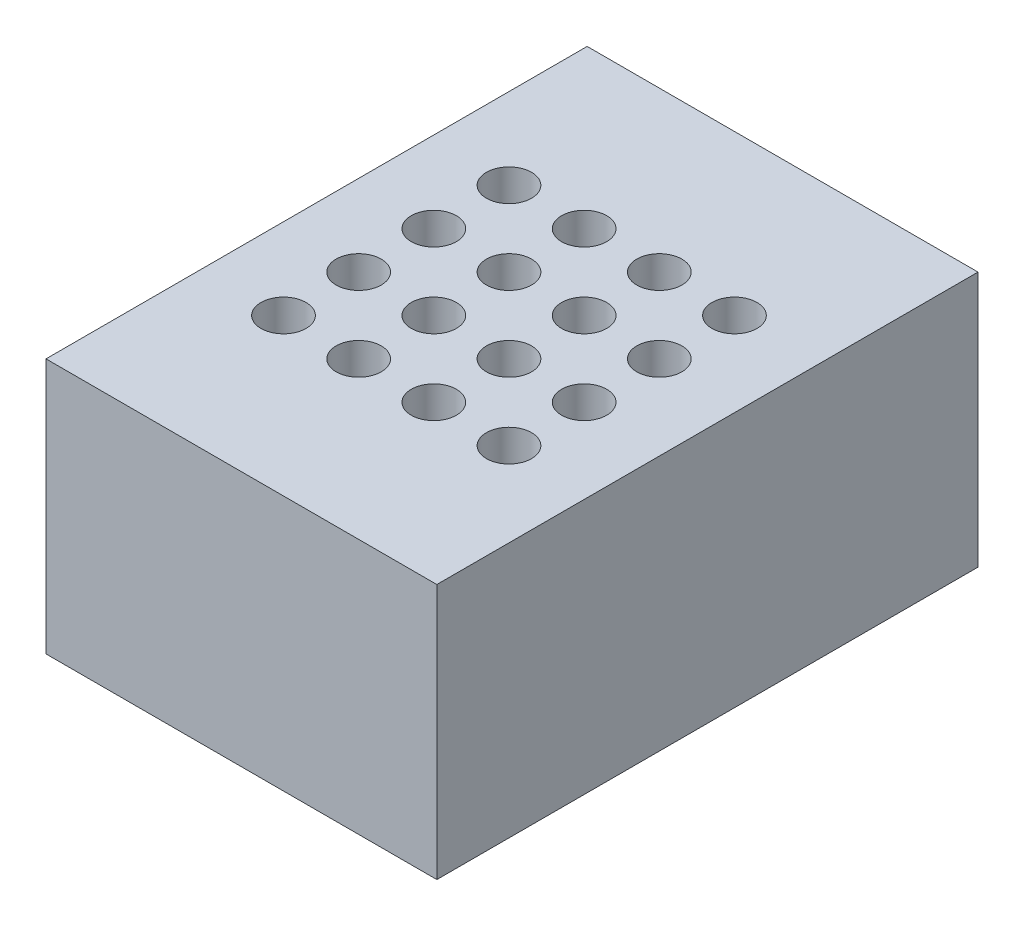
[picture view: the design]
ISO-10303-21;
HEADER;
FILE_DESCRIPTION(('STEP AP214'),'2;1');
FILE_NAME('part.step','',(''),(''),'','','');
FILE_SCHEMA(('AUTOMOTIVE_DESIGN { 1 0 10303 214 1 1 1 1 }'));
ENDSEC;
DATA;
#1=APPLICATION_CONTEXT('core data for automotive mechanical design processes');
#2=APPLICATION_PROTOCOL_DEFINITION('international standard','automotive_design',2000,#1);
#3=PRODUCT_CONTEXT('',#1,'mechanical');
#4=PRODUCT('Part','Part','',(#3));
#5=PRODUCT_RELATED_PRODUCT_CATEGORY('part','',(#4));
#6=PRODUCT_DEFINITION_FORMATION('','',#4);
#7=PRODUCT_DEFINITION_CONTEXT('part definition',#1,'design');
#8=PRODUCT_DEFINITION('design','',#6,#7);
#9=PRODUCT_DEFINITION_SHAPE('','',#8);
#10=(LENGTH_UNIT() NAMED_UNIT(*) SI_UNIT(.MILLI.,.METRE.));
#11=(NAMED_UNIT(*) PLANE_ANGLE_UNIT() SI_UNIT($,.RADIAN.));
#12=(NAMED_UNIT(*) SI_UNIT($,.STERADIAN.) SOLID_ANGLE_UNIT());
#13=UNCERTAINTY_MEASURE_WITH_UNIT(LENGTH_MEASURE(1.E-05),#10,'distance_accuracy_value','');
#14=(GEOMETRIC_REPRESENTATION_CONTEXT(3) GLOBAL_UNCERTAINTY_ASSIGNED_CONTEXT((#13)) GLOBAL_UNIT_ASSIGNED_CONTEXT((#10,
#11,#12)) REPRESENTATION_CONTEXT('',''));
#15=CARTESIAN_POINT('',(0.,0.,0.));
#16=DIRECTION('',(0.,0.,1.));
#17=DIRECTION('',(1.,0.,0.));
#18=AXIS2_PLACEMENT_3D('',#15,#16,#17);
#19=CARTESIAN_POINT('',(0.,8.5,0.));
#20=DIRECTION('',(1.,0.,0.));
#21=DIRECTION('',(0.,0.,-1.));
#22=AXIS2_PLACEMENT_3D('',#19,#20,#21);
#23=PLANE('',#22);
#24=DIRECTION('',(0.,0.,1.));
#25=VECTOR('',#24,1.);
#26=CARTESIAN_POINT('',(0.,0.,0.));
#27=LINE('',#26,#25);
#28=CARTESIAN_POINT('',(0.,0.,-18.));
#29=VERTEX_POINT('',#28);
#30=CARTESIAN_POINT('',(0.,0.,0.));
#31=VERTEX_POINT('',#30);
#32=EDGE_CURVE('E95',#29,#31,#27,.T.);
#33=ORIENTED_EDGE('',*,*,#32,.T.);
#34=DIRECTION('',(0.,-1.,0.));
#35=VECTOR('',#34,1.);
#36=CARTESIAN_POINT('',(0.,8.5,0.));
#37=LINE('',#36,#35);
#38=CARTESIAN_POINT('',(0.,8.5,0.));
#39=VERTEX_POINT('',#38);
#40=EDGE_CURVE('E11',#39,#31,#37,.T.);
#41=ORIENTED_EDGE('',*,*,#40,.F.);
#42=DIRECTION('',(0.,0.,1.));
#43=VECTOR('',#42,1.);
#44=CARTESIAN_POINT('',(0.,8.5,0.));
#45=LINE('',#44,#43);
#46=CARTESIAN_POINT('',(0.,8.5,-18.));
#47=VERTEX_POINT('',#46);
#48=EDGE_CURVE('E83',#47,#39,#45,.T.);
#49=ORIENTED_EDGE('',*,*,#48,.F.);
#50=DIRECTION('',(0.,-1.,0.));
#51=VECTOR('',#50,1.);
#52=CARTESIAN_POINT('',(0.,8.5,-18.));
#53=LINE('',#52,#51);
#54=EDGE_CURVE('E91',#47,#29,#53,.T.);
#55=ORIENTED_EDGE('',*,*,#54,.T.);
#56=EDGE_LOOP('',(#33,#41,#49,#55));
#57=FACE_BOUND('',#56,.T.);
#58=ADVANCED_FACE('F32',(#57),#23,.F.);
#59=CARTESIAN_POINT('',(0.,8.5,0.));
#60=DIRECTION('',(0.,0.,-1.));
#61=DIRECTION('',(-1.,0.,0.));
#62=AXIS2_PLACEMENT_3D('',#59,#60,#61);
#63=PLANE('',#62);
#64=DIRECTION('',(1.,0.,0.));
#65=VECTOR('',#64,1.);
#66=CARTESIAN_POINT('',(0.,0.,0.));
#67=LINE('',#66,#65);
#68=CARTESIAN_POINT('',(13.,0.,0.));
#69=VERTEX_POINT('',#68);
#70=EDGE_CURVE('E87',#31,#69,#67,.T.);
#71=ORIENTED_EDGE('',*,*,#70,.T.);
#72=DIRECTION('',(0.,-1.,0.));
#73=VECTOR('',#72,1.);
#74=CARTESIAN_POINT('',(13.,8.5,0.));
#75=LINE('',#74,#73);
#76=CARTESIAN_POINT('',(13.,8.5,0.));
#77=VERTEX_POINT('',#76);
#78=EDGE_CURVE('E40',#77,#69,#75,.T.);
#79=ORIENTED_EDGE('',*,*,#78,.F.);
#80=DIRECTION('',(1.,0.,0.));
#81=VECTOR('',#80,1.);
#82=CARTESIAN_POINT('',(0.,8.5,0.));
#83=LINE('',#82,#81);
#84=EDGE_CURVE('E78',#39,#77,#83,.T.);
#85=ORIENTED_EDGE('',*,*,#84,.F.);
#86=ORIENTED_EDGE('',*,*,#40,.T.);
#87=EDGE_LOOP('',(#71,#79,#85,#86));
#88=FACE_BOUND('',#87,.T.);
#89=ADVANCED_FACE('F86',(#88),#63,.F.);
#90=CARTESIAN_POINT('',(13.,8.5,0.));
#91=DIRECTION('',(-1.,0.,0.));
#92=DIRECTION('',(0.,0.,1.));
#93=AXIS2_PLACEMENT_3D('',#90,#91,#92);
#94=PLANE('',#93);
#95=DIRECTION('',(0.,0.,-1.));
#96=VECTOR('',#95,1.);
#97=CARTESIAN_POINT('',(13.,0.,0.));
#98=LINE('',#97,#96);
#99=CARTESIAN_POINT('',(13.,0.,-18.));
#100=VERTEX_POINT('',#99);
#101=EDGE_CURVE('E65',#69,#100,#98,.T.);
#102=ORIENTED_EDGE('',*,*,#101,.T.);
#103=DIRECTION('',(0.,-1.,0.));
#104=VECTOR('',#103,1.);
#105=CARTESIAN_POINT('',(13.,8.5,-18.));
#106=LINE('',#105,#104);
#107=CARTESIAN_POINT('',(13.,8.5,-18.));
#108=VERTEX_POINT('',#107);
#109=EDGE_CURVE('E88',#108,#100,#106,.T.);
#110=ORIENTED_EDGE('',*,*,#109,.F.);
#111=DIRECTION('',(0.,0.,-1.));
#112=VECTOR('',#111,1.);
#113=CARTESIAN_POINT('',(13.,8.5,0.));
#114=LINE('',#113,#112);
#115=EDGE_CURVE('E81',#77,#108,#114,.T.);
#116=ORIENTED_EDGE('',*,*,#115,.F.);
#117=ORIENTED_EDGE('',*,*,#78,.T.);
#118=EDGE_LOOP('',(#102,#110,#116,#117));
#119=FACE_BOUND('',#118,.T.);
#120=ADVANCED_FACE('F89',(#119),#94,.F.);
#121=CARTESIAN_POINT('',(0.,8.5,-18.));
#122=DIRECTION('',(0.,0.,1.));
#123=DIRECTION('',(1.,0.,0.));
#124=AXIS2_PLACEMENT_3D('',#121,#122,#123);
#125=PLANE('',#124);
#126=DIRECTION('',(-1.,0.,0.));
#127=VECTOR('',#126,1.);
#128=CARTESIAN_POINT('',(0.,0.,-18.));
#129=LINE('',#128,#127);
#130=EDGE_CURVE('E71',#100,#29,#129,.T.);
#131=ORIENTED_EDGE('',*,*,#130,.T.);
#132=ORIENTED_EDGE('',*,*,#54,.F.);
#133=DIRECTION('',(-1.,0.,0.));
#134=VECTOR('',#133,1.);
#135=CARTESIAN_POINT('',(0.,8.5,-18.));
#136=LINE('',#135,#134);
#137=EDGE_CURVE('E48',#108,#47,#136,.T.);
#138=ORIENTED_EDGE('',*,*,#137,.F.);
#139=ORIENTED_EDGE('',*,*,#109,.T.);
#140=EDGE_LOOP('',(#131,#132,#138,#139));
#141=FACE_BOUND('',#140,.T.);
#142=ADVANCED_FACE('F103',(#141),#125,.F.);
#143=CARTESIAN_POINT('',(0.,8.5,0.));
#144=DIRECTION('',(0.,-1.,0.));
#145=DIRECTION('',(0.,0.,-1.));
#146=AXIS2_PLACEMENT_3D('',#143,#144,#145);
#147=PLANE('',#146);
#148=CARTESIAN_POINT('',(10.2000000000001,8.5,-5.2));
#149=DIRECTION('',(0.,1.,0.));
#150=DIRECTION('',(0.,0.,1.));
#151=AXIS2_PLACEMENT_3D('',#148,#149,#150);
#152=CIRCLE('',#151,0.75);
#153=CARTESIAN_POINT('',(10.2000000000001,8.5,-4.45));
#154=VERTEX_POINT('',#153);
#155=EDGE_CURVE('E199',#154,#154,#152,.T.);
#156=ORIENTED_EDGE('',*,*,#155,.F.);
#157=EDGE_LOOP('',(#156));
#158=FACE_BOUND('',#157,.T.);
#159=CARTESIAN_POINT('',(10.2000000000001,8.5,-7.7));
#160=DIRECTION('',(0.,1.,0.));
#161=DIRECTION('',(0.,0.,1.));
#162=AXIS2_PLACEMENT_3D('',#159,#160,#161);
#163=CIRCLE('',#162,0.75);
#164=CARTESIAN_POINT('',(10.2000000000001,8.5,-6.95));
#165=VERTEX_POINT('',#164);
#166=EDGE_CURVE('E193',#165,#165,#163,.T.);
#167=ORIENTED_EDGE('',*,*,#166,.F.);
#168=EDGE_LOOP('',(#167));
#169=FACE_BOUND('',#168,.T.);
#170=CARTESIAN_POINT('',(10.2,8.5,-10.2));
#171=DIRECTION('',(0.,1.,0.));
#172=DIRECTION('',(0.,0.,1.));
#173=AXIS2_PLACEMENT_3D('',#170,#171,#172);
#174=CIRCLE('',#173,0.75);
#175=CARTESIAN_POINT('',(10.2,8.5,-9.45));
#176=VERTEX_POINT('',#175);
#177=EDGE_CURVE('E187',#176,#176,#174,.T.);
#178=ORIENTED_EDGE('',*,*,#177,.F.);
#179=EDGE_LOOP('',(#178));
#180=FACE_BOUND('',#179,.T.);
#181=CARTESIAN_POINT('',(2.70000000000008,8.5,-5.19999999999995));
#182=DIRECTION('',(0.,1.,0.));
#183=DIRECTION('',(0.,0.,1.));
#184=AXIS2_PLACEMENT_3D('',#181,#182,#183);
#185=CIRCLE('',#184,0.75);
#186=CARTESIAN_POINT('',(2.70000000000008,8.5,-4.44999999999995));
#187=VERTEX_POINT('',#186);
#188=EDGE_CURVE('E181',#187,#187,#185,.T.);
#189=ORIENTED_EDGE('',*,*,#188,.F.);
#190=EDGE_LOOP('',(#189));
#191=FACE_BOUND('',#190,.T.);
#192=CARTESIAN_POINT('',(5.20000000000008,8.5,-5.19999999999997));
#193=DIRECTION('',(0.,1.,0.));
#194=DIRECTION('',(0.,0.,1.));
#195=AXIS2_PLACEMENT_3D('',#192,#193,#194);
#196=CIRCLE('',#195,0.75);
#197=CARTESIAN_POINT('',(5.20000000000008,8.5,-4.44999999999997));
#198=VERTEX_POINT('',#197);
#199=EDGE_CURVE('E175',#198,#198,#196,.T.);
#200=ORIENTED_EDGE('',*,*,#199,.F.);
#201=EDGE_LOOP('',(#200));
#202=FACE_BOUND('',#201,.T.);
#203=CARTESIAN_POINT('',(7.70000000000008,8.5,-5.19999999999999));
#204=DIRECTION('',(0.,1.,0.));
#205=DIRECTION('',(0.,0.,1.));
#206=AXIS2_PLACEMENT_3D('',#203,#204,#205);
#207=CIRCLE('',#206,0.750000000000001);
#208=CARTESIAN_POINT('',(7.70000000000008,8.5,-4.44999999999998));
#209=VERTEX_POINT('',#208);
#210=EDGE_CURVE('E169',#209,#209,#207,.T.);
#211=ORIENTED_EDGE('',*,*,#210,.F.);
#212=EDGE_LOOP('',(#211));
#213=FACE_BOUND('',#212,.T.);
#214=CARTESIAN_POINT('',(2.70000000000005,8.5,-7.69999999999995));
#215=DIRECTION('',(0.,1.,0.));
#216=DIRECTION('',(0.,0.,1.));
#217=AXIS2_PLACEMENT_3D('',#214,#215,#216);
#218=CIRCLE('',#217,0.75);
#219=CARTESIAN_POINT('',(2.70000000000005,8.5,-6.94999999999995));
#220=VERTEX_POINT('',#219);
#221=EDGE_CURVE('E163',#220,#220,#218,.T.);
#222=ORIENTED_EDGE('',*,*,#221,.F.);
#223=EDGE_LOOP('',(#222));
#224=FACE_BOUND('',#223,.T.);
#225=CARTESIAN_POINT('',(5.20000000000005,8.5,-7.69999999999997));
#226=DIRECTION('',(0.,1.,0.));
#227=DIRECTION('',(0.,0.,1.));
#228=AXIS2_PLACEMENT_3D('',#225,#226,#227);
#229=CIRCLE('',#228,0.75);
#230=CARTESIAN_POINT('',(5.20000000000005,8.5,-6.94999999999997));
#231=VERTEX_POINT('',#230);
#232=EDGE_CURVE('E157',#231,#231,#229,.T.);
#233=ORIENTED_EDGE('',*,*,#232,.F.);
#234=EDGE_LOOP('',(#233));
#235=FACE_BOUND('',#234,.T.);
#236=CARTESIAN_POINT('',(7.70000000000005,8.5,-7.69999999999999));
#237=DIRECTION('',(0.,1.,0.));
#238=DIRECTION('',(0.,0.,1.));
#239=AXIS2_PLACEMENT_3D('',#236,#237,#238);
#240=CIRCLE('',#239,0.749999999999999);
#241=CARTESIAN_POINT('',(7.70000000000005,8.5,-6.94999999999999));
#242=VERTEX_POINT('',#241);
#243=EDGE_CURVE('E151',#242,#242,#240,.T.);
#244=ORIENTED_EDGE('',*,*,#243,.F.);
#245=EDGE_LOOP('',(#244));
#246=FACE_BOUND('',#245,.T.);
#247=CARTESIAN_POINT('',(2.70000000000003,8.5,-10.1999999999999));
#248=DIRECTION('',(0.,1.,0.));
#249=DIRECTION('',(0.,0.,1.));
#250=AXIS2_PLACEMENT_3D('',#247,#248,#249);
#251=CIRCLE('',#250,0.75);
#252=CARTESIAN_POINT('',(2.70000000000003,8.5,-9.44999999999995));
#253=VERTEX_POINT('',#252);
#254=EDGE_CURVE('E145',#253,#253,#251,.T.);
#255=ORIENTED_EDGE('',*,*,#254,.F.);
#256=EDGE_LOOP('',(#255));
#257=FACE_BOUND('',#256,.T.);
#258=CARTESIAN_POINT('',(5.20000000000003,8.5,-10.2));
#259=DIRECTION('',(0.,1.,0.));
#260=DIRECTION('',(0.,0.,1.));
#261=AXIS2_PLACEMENT_3D('',#258,#259,#260);
#262=CIRCLE('',#261,0.75);
#263=CARTESIAN_POINT('',(5.20000000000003,8.5,-9.44999999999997));
#264=VERTEX_POINT('',#263);
#265=EDGE_CURVE('E139',#264,#264,#262,.T.);
#266=ORIENTED_EDGE('',*,*,#265,.F.);
#267=EDGE_LOOP('',(#266));
#268=FACE_BOUND('',#267,.T.);
#269=CARTESIAN_POINT('',(7.70000000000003,8.5,-10.2));
#270=DIRECTION('',(0.,1.,0.));
#271=DIRECTION('',(0.,0.,1.));
#272=AXIS2_PLACEMENT_3D('',#269,#270,#271);
#273=CIRCLE('',#272,0.75);
#274=CARTESIAN_POINT('',(7.70000000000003,8.5,-9.44999999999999));
#275=VERTEX_POINT('',#274);
#276=EDGE_CURVE('E133',#275,#275,#273,.T.);
#277=ORIENTED_EDGE('',*,*,#276,.F.);
#278=EDGE_LOOP('',(#277));
#279=FACE_BOUND('',#278,.T.);
#280=CARTESIAN_POINT('',(2.7,8.5,-12.7));
#281=DIRECTION('',(0.,1.,0.));
#282=DIRECTION('',(0.,0.,1.));
#283=AXIS2_PLACEMENT_3D('',#280,#281,#282);
#284=CIRCLE('',#283,0.75);
#285=CARTESIAN_POINT('',(2.7,8.5,-11.9499999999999));
#286=VERTEX_POINT('',#285);
#287=EDGE_CURVE('E127',#286,#286,#284,.T.);
#288=ORIENTED_EDGE('',*,*,#287,.F.);
#289=EDGE_LOOP('',(#288));
#290=FACE_BOUND('',#289,.T.);
#291=CARTESIAN_POINT('',(5.2,8.5,-12.7));
#292=DIRECTION('',(0.,1.,0.));
#293=DIRECTION('',(0.,0.,1.));
#294=AXIS2_PLACEMENT_3D('',#291,#292,#293);
#295=CIRCLE('',#294,0.75);
#296=CARTESIAN_POINT('',(5.2,8.5,-11.95));
#297=VERTEX_POINT('',#296);
#298=EDGE_CURVE('E121',#297,#297,#295,.T.);
#299=ORIENTED_EDGE('',*,*,#298,.F.);
#300=EDGE_LOOP('',(#299));
#301=FACE_BOUND('',#300,.T.);
#302=CARTESIAN_POINT('',(7.7,8.5,-12.7));
#303=DIRECTION('',(0.,1.,0.));
#304=DIRECTION('',(0.,0.,1.));
#305=AXIS2_PLACEMENT_3D('',#302,#303,#304);
#306=CIRCLE('',#305,0.75);
#307=CARTESIAN_POINT('',(7.7,8.5,-11.95));
#308=VERTEX_POINT('',#307);
#309=EDGE_CURVE('E115',#308,#308,#306,.T.);
#310=ORIENTED_EDGE('',*,*,#309,.F.);
#311=EDGE_LOOP('',(#310));
#312=FACE_BOUND('',#311,.T.);
#313=CARTESIAN_POINT('',(10.2,8.5,-12.7));
#314=DIRECTION('',(0.,1.,0.));
#315=DIRECTION('',(0.,0.,1.));
#316=AXIS2_PLACEMENT_3D('',#313,#314,#315);
#317=CIRCLE('',#316,0.75);
#318=CARTESIAN_POINT('',(10.2,8.5,-11.95));
#319=VERTEX_POINT('',#318);
#320=EDGE_CURVE('E109',#319,#319,#317,.T.);
#321=ORIENTED_EDGE('',*,*,#320,.F.);
#322=EDGE_LOOP('',(#321));
#323=FACE_BOUND('',#322,.T.);
#324=ORIENTED_EDGE('',*,*,#48,.T.);
#325=ORIENTED_EDGE('',*,*,#84,.T.);
#326=ORIENTED_EDGE('',*,*,#115,.T.);
#327=ORIENTED_EDGE('',*,*,#137,.T.);
#328=EDGE_LOOP('',(#324,#325,#326,#327));
#329=FACE_BOUND('',#328,.T.);
#330=ADVANCED_FACE('F79',(#158,#169,#180,#191,#202,#213,#224,#235,#246,#257,#268,#279,#290,#301,
#312,#323,#329),#147,.F.);
#331=CARTESIAN_POINT('',(0.,0.,0.));
#332=DIRECTION('',(0.,-1.,0.));
#333=DIRECTION('',(0.,0.,-1.));
#334=AXIS2_PLACEMENT_3D('',#331,#332,#333);
#335=PLANE('',#334);
#336=ORIENTED_EDGE('',*,*,#32,.F.);
#337=ORIENTED_EDGE('',*,*,#130,.F.);
#338=ORIENTED_EDGE('',*,*,#101,.F.);
#339=ORIENTED_EDGE('',*,*,#70,.F.);
#340=EDGE_LOOP('',(#336,#337,#338,#339));
#341=FACE_BOUND('',#340,.T.);
#342=ADVANCED_FACE('F106',(#341),#335,.T.);
#343=CARTESIAN_POINT('',(10.2,1.5,-12.7));
#344=DIRECTION('',(0.,1.,0.));
#345=DIRECTION('',(0.,0.,1.));
#346=AXIS2_PLACEMENT_3D('',#343,#344,#345);
#347=CYLINDRICAL_SURFACE('',#346,0.75);
#348=CARTESIAN_POINT('',(10.2,1.5,-12.7));
#349=DIRECTION('',(0.,1.,0.));
#350=DIRECTION('',(0.,0.,1.));
#351=AXIS2_PLACEMENT_3D('',#348,#349,#350);
#352=CIRCLE('',#351,0.75);
#353=CARTESIAN_POINT('',(10.2,1.5,-11.95));
#354=VERTEX_POINT('',#353);
#355=EDGE_CURVE('E98',#354,#354,#352,.T.);
#356=CARTESIAN_POINT('',(10.2,1.5,-11.95));
#357=CARTESIAN_POINT('',(10.2,1.57291666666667,-11.95));
#358=CARTESIAN_POINT('',(10.2,1.64583333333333,-11.95));
#359=CARTESIAN_POINT('',(10.2,1.79166666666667,-11.95));
#360=CARTESIAN_POINT('',(10.2,1.86458333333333,-11.95));
#361=CARTESIAN_POINT('',(10.2,2.01041666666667,-11.95));
#362=CARTESIAN_POINT('',(10.2,2.08333333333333,-11.95));
#363=CARTESIAN_POINT('',(10.2,2.22916666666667,-11.95));
#364=CARTESIAN_POINT('',(10.2,2.30208333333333,-11.95));
#365=CARTESIAN_POINT('',(10.2,2.44791666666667,-11.95));
#366=CARTESIAN_POINT('',(10.2,2.52083333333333,-11.95));
#367=CARTESIAN_POINT('',(10.2,2.66666666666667,-11.95));
#368=CARTESIAN_POINT('',(10.2,2.73958333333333,-11.95));
#369=CARTESIAN_POINT('',(10.2,2.88541666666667,-11.95));
#370=CARTESIAN_POINT('',(10.2,2.95833333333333,-11.95));
#371=CARTESIAN_POINT('',(10.2,3.10416666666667,-11.95));
#372=CARTESIAN_POINT('',(10.2,3.17708333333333,-11.95));
#373=CARTESIAN_POINT('',(10.2,3.32291666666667,-11.95));
#374=CARTESIAN_POINT('',(10.2,3.39583333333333,-11.95));
#375=CARTESIAN_POINT('',(10.2,3.54166666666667,-11.95));
#376=CARTESIAN_POINT('',(10.2,3.61458333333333,-11.95));
#377=CARTESIAN_POINT('',(10.2,3.76041666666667,-11.95));
#378=CARTESIAN_POINT('',(10.2,3.83333333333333,-11.95));
#379=CARTESIAN_POINT('',(10.2,3.97916666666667,-11.95));
#380=CARTESIAN_POINT('',(10.2,4.05208333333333,-11.95));
#381=CARTESIAN_POINT('',(10.2,4.19791666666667,-11.95));
#382=CARTESIAN_POINT('',(10.2,4.27083333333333,-11.95));
#383=CARTESIAN_POINT('',(10.2,4.41666666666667,-11.95));
#384=CARTESIAN_POINT('',(10.2,4.48958333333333,-11.95));
#385=CARTESIAN_POINT('',(10.2,4.63541666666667,-11.95));
#386=CARTESIAN_POINT('',(10.2,4.70833333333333,-11.95));
#387=CARTESIAN_POINT('',(10.2,4.85416666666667,-11.95));
#388=CARTESIAN_POINT('',(10.2,4.92708333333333,-11.95));
#389=CARTESIAN_POINT('',(10.2,5.07291666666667,-11.95));
#390=CARTESIAN_POINT('',(10.2,5.14583333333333,-11.95));
#391=CARTESIAN_POINT('',(10.2,5.29166666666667,-11.95));
#392=CARTESIAN_POINT('',(10.2,5.36458333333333,-11.95));
#393=CARTESIAN_POINT('',(10.2,5.51041666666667,-11.95));
#394=CARTESIAN_POINT('',(10.2,5.58333333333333,-11.95));
#395=CARTESIAN_POINT('',(10.2,5.72916666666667,-11.95));
#396=CARTESIAN_POINT('',(10.2,5.80208333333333,-11.95));
#397=CARTESIAN_POINT('',(10.2,5.94791666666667,-11.95));
#398=CARTESIAN_POINT('',(10.2,6.02083333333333,-11.95));
#399=CARTESIAN_POINT('',(10.2,6.16666666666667,-11.95));
#400=CARTESIAN_POINT('',(10.2,6.23958333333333,-11.95));
#401=CARTESIAN_POINT('',(10.2,6.38541666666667,-11.95));
#402=CARTESIAN_POINT('',(10.2,6.45833333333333,-11.95));
#403=CARTESIAN_POINT('',(10.2,6.60416666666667,-11.95));
#404=CARTESIAN_POINT('',(10.2,6.67708333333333,-11.95));
#405=CARTESIAN_POINT('',(10.2,6.82291666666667,-11.95));
#406=CARTESIAN_POINT('',(10.2,6.89583333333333,-11.95));
#407=CARTESIAN_POINT('',(10.2,7.04166666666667,-11.95));
#408=CARTESIAN_POINT('',(10.2,7.11458333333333,-11.95));
#409=CARTESIAN_POINT('',(10.2,7.26041666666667,-11.95));
#410=CARTESIAN_POINT('',(10.2,7.33333333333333,-11.95));
#411=CARTESIAN_POINT('',(10.2,7.47916666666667,-11.95));
#412=CARTESIAN_POINT('',(10.2,7.55208333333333,-11.95));
#413=CARTESIAN_POINT('',(10.2,7.69791666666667,-11.95));
#414=CARTESIAN_POINT('',(10.2,7.77083333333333,-11.95));
#415=CARTESIAN_POINT('',(10.2,7.91666666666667,-11.95));
#416=CARTESIAN_POINT('',(10.2,7.98958333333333,-11.95));
#417=CARTESIAN_POINT('',(10.2,8.13541666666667,-11.95));
#418=CARTESIAN_POINT('',(10.2,8.20833333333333,-11.95));
#419=CARTESIAN_POINT('',(10.2,8.35416666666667,-11.95));
#420=CARTESIAN_POINT('',(10.2,8.42708333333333,-11.95));
#421=CARTESIAN_POINT('',(10.2,8.5,-11.95));
#422=B_SPLINE_CURVE_WITH_KNOTS('',3,(#356,#357,#358,#359,#360,#361,#362,#363,#364,#365,#366,
#367,#368,#369,#370,#371,#372,#373,#374,#375,#376,#377,#378,#379,#380,#381,#382,#383,#384,#385,
#386,#387,#388,#389,#390,#391,#392,#393,#394,#395,#396,#397,#398,#399,#400,#401,#402,#403,#404,
#405,#406,#407,#408,#409,#410,#411,#412,#413,#414,#415,#416,#417,#418,#419,#420,#421),
.UNSPECIFIED.,.F.,.F.,(4,2,2,2,2,2,2,2,2,2,2,2,2,2,2,2,2,2,2,2,2,2,2,2,2,2,2,2,2,2,2,2,4),(0.,
0.21875,0.4375,0.65625,0.875,1.09375,1.3125,1.53125,1.75,1.96875,2.1875,2.40625,2.625,2.84375,
3.0625,3.28125,3.5,3.71875,3.9375,4.15625,4.375,4.59375,4.8125,5.03125,5.25,5.46875,5.6875,
5.90625,6.125,6.34375,6.5625,6.78125,7.),.UNSPECIFIED.);
#423=EDGE_CURVE('BSEAM247',#354,#319,#422,.T.);
#424=ORIENTED_EDGE('',*,*,#355,.F.);
#425=ORIENTED_EDGE('',*,*,#320,.T.);
#426=ORIENTED_EDGE('',*,*,#423,.T.);
#427=ORIENTED_EDGE('',*,*,#423,.F.);
#428=EDGE_LOOP('',(#424,#426,#425,#427));
#429=FACE_BOUND('',#428,.T.);
#430=ADVANCED_FACE('F247',(#429),#347,.F.);
#431=CARTESIAN_POINT('',(10.2,1.5,-12.7));
#432=DIRECTION('',(0.,1.,0.));
#433=DIRECTION('',(0.,0.,1.));
#434=AXIS2_PLACEMENT_3D('',#431,#432,#433);
#435=PLANE('',#434);
#436=ORIENTED_EDGE('',*,*,#355,.T.);
#437=EDGE_LOOP('',(#436));
#438=FACE_BOUND('',#437,.T.);
#439=ADVANCED_FACE('F249',(#438),#435,.T.);
#440=CARTESIAN_POINT('',(7.7,1.5,-12.7));
#441=DIRECTION('',(0.,1.,0.));
#442=DIRECTION('',(0.,0.,1.));
#443=AXIS2_PLACEMENT_3D('',#440,#441,#442);
#444=CYLINDRICAL_SURFACE('',#443,0.75);
#445=CARTESIAN_POINT('',(7.7,1.5,-12.7));
#446=DIRECTION('',(0.,1.,0.));
#447=DIRECTION('',(0.,0.,1.));
#448=AXIS2_PLACEMENT_3D('',#445,#446,#447);
#449=CIRCLE('',#448,0.75);
#450=CARTESIAN_POINT('',(7.7,1.5,-11.95));
#451=VERTEX_POINT('',#450);
#452=EDGE_CURVE('E112',#451,#451,#449,.T.);
#453=CARTESIAN_POINT('',(7.7,1.5,-11.95));
#454=CARTESIAN_POINT('',(7.7,1.57291666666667,-11.95));
#455=CARTESIAN_POINT('',(7.7,1.64583333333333,-11.95));
#456=CARTESIAN_POINT('',(7.7,1.79166666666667,-11.95));
#457=CARTESIAN_POINT('',(7.7,1.86458333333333,-11.95));
#458=CARTESIAN_POINT('',(7.7,2.01041666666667,-11.95));
#459=CARTESIAN_POINT('',(7.7,2.08333333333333,-11.95));
#460=CARTESIAN_POINT('',(7.7,2.22916666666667,-11.95));
#461=CARTESIAN_POINT('',(7.7,2.30208333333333,-11.95));
#462=CARTESIAN_POINT('',(7.7,2.44791666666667,-11.95));
#463=CARTESIAN_POINT('',(7.7,2.52083333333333,-11.95));
#464=CARTESIAN_POINT('',(7.7,2.66666666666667,-11.95));
#465=CARTESIAN_POINT('',(7.7,2.73958333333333,-11.95));
#466=CARTESIAN_POINT('',(7.7,2.88541666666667,-11.95));
#467=CARTESIAN_POINT('',(7.7,2.95833333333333,-11.95));
#468=CARTESIAN_POINT('',(7.7,3.10416666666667,-11.95));
#469=CARTESIAN_POINT('',(7.7,3.17708333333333,-11.95));
#470=CARTESIAN_POINT('',(7.7,3.32291666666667,-11.95));
#471=CARTESIAN_POINT('',(7.7,3.39583333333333,-11.95));
#472=CARTESIAN_POINT('',(7.7,3.54166666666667,-11.95));
#473=CARTESIAN_POINT('',(7.7,3.61458333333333,-11.95));
#474=CARTESIAN_POINT('',(7.7,3.76041666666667,-11.95));
#475=CARTESIAN_POINT('',(7.7,3.83333333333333,-11.95));
#476=CARTESIAN_POINT('',(7.7,3.97916666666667,-11.95));
#477=CARTESIAN_POINT('',(7.7,4.05208333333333,-11.95));
#478=CARTESIAN_POINT('',(7.7,4.19791666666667,-11.95));
#479=CARTESIAN_POINT('',(7.7,4.27083333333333,-11.95));
#480=CARTESIAN_POINT('',(7.7,4.41666666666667,-11.95));
#481=CARTESIAN_POINT('',(7.7,4.48958333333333,-11.95));
#482=CARTESIAN_POINT('',(7.7,4.63541666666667,-11.95));
#483=CARTESIAN_POINT('',(7.7,4.70833333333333,-11.95));
#484=CARTESIAN_POINT('',(7.7,4.85416666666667,-11.95));
#485=CARTESIAN_POINT('',(7.7,4.92708333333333,-11.95));
#486=CARTESIAN_POINT('',(7.7,5.07291666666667,-11.95));
#487=CARTESIAN_POINT('',(7.7,5.14583333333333,-11.95));
#488=CARTESIAN_POINT('',(7.7,5.29166666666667,-11.95));
#489=CARTESIAN_POINT('',(7.7,5.36458333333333,-11.95));
#490=CARTESIAN_POINT('',(7.7,5.51041666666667,-11.95));
#491=CARTESIAN_POINT('',(7.7,5.58333333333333,-11.95));
#492=CARTESIAN_POINT('',(7.7,5.72916666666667,-11.95));
#493=CARTESIAN_POINT('',(7.7,5.80208333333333,-11.95));
#494=CARTESIAN_POINT('',(7.7,5.94791666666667,-11.95));
#495=CARTESIAN_POINT('',(7.7,6.02083333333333,-11.95));
#496=CARTESIAN_POINT('',(7.7,6.16666666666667,-11.95));
#497=CARTESIAN_POINT('',(7.7,6.23958333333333,-11.95));
#498=CARTESIAN_POINT('',(7.7,6.38541666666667,-11.95));
#499=CARTESIAN_POINT('',(7.7,6.45833333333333,-11.95));
#500=CARTESIAN_POINT('',(7.7,6.60416666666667,-11.95));
#501=CARTESIAN_POINT('',(7.7,6.67708333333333,-11.95));
#502=CARTESIAN_POINT('',(7.7,6.82291666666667,-11.95));
#503=CARTESIAN_POINT('',(7.7,6.89583333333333,-11.95));
#504=CARTESIAN_POINT('',(7.7,7.04166666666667,-11.95));
#505=CARTESIAN_POINT('',(7.7,7.11458333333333,-11.95));
#506=CARTESIAN_POINT('',(7.7,7.26041666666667,-11.95));
#507=CARTESIAN_POINT('',(7.7,7.33333333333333,-11.95));
#508=CARTESIAN_POINT('',(7.7,7.47916666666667,-11.95));
#509=CARTESIAN_POINT('',(7.7,7.55208333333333,-11.95));
#510=CARTESIAN_POINT('',(7.7,7.69791666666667,-11.95));
#511=CARTESIAN_POINT('',(7.7,7.77083333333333,-11.95));
#512=CARTESIAN_POINT('',(7.7,7.91666666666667,-11.95));
#513=CARTESIAN_POINT('',(7.7,7.98958333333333,-11.95));
#514=CARTESIAN_POINT('',(7.7,8.13541666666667,-11.95));
#515=CARTESIAN_POINT('',(7.7,8.20833333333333,-11.95));
#516=CARTESIAN_POINT('',(7.7,8.35416666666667,-11.95));
#517=CARTESIAN_POINT('',(7.7,8.42708333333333,-11.95));
#518=CARTESIAN_POINT('',(7.7,8.5,-11.95));
#519=B_SPLINE_CURVE_WITH_KNOTS('',3,(#453,#454,#455,#456,#457,#458,#459,#460,#461,#462,#463,
#464,#465,#466,#467,#468,#469,#470,#471,#472,#473,#474,#475,#476,#477,#478,#479,#480,#481,#482,
#483,#484,#485,#486,#487,#488,#489,#490,#491,#492,#493,#494,#495,#496,#497,#498,#499,#500,#501,
#502,#503,#504,#505,#506,#507,#508,#509,#510,#511,#512,#513,#514,#515,#516,#517,#518),
.UNSPECIFIED.,.F.,.F.,(4,2,2,2,2,2,2,2,2,2,2,2,2,2,2,2,2,2,2,2,2,2,2,2,2,2,2,2,2,2,2,2,4),(0.,
0.21875,0.4375,0.65625,0.875,1.09375,1.3125,1.53125,1.75,1.96875,2.1875,2.40625,2.625,2.84375,
3.0625,3.28125,3.5,3.71875,3.9375,4.15625,4.375,4.59375,4.8125,5.03125,5.25,5.46875,5.6875,
5.90625,6.125,6.34375,6.5625,6.78125,7.),.UNSPECIFIED.);
#520=EDGE_CURVE('BSEAM256',#451,#308,#519,.T.);
#521=ORIENTED_EDGE('',*,*,#452,.F.);
#522=ORIENTED_EDGE('',*,*,#309,.T.);
#523=ORIENTED_EDGE('',*,*,#520,.T.);
#524=ORIENTED_EDGE('',*,*,#520,.F.);
#525=EDGE_LOOP('',(#521,#523,#522,#524));
#526=FACE_BOUND('',#525,.T.);
#527=ADVANCED_FACE('F256',(#526),#444,.F.);
#528=CARTESIAN_POINT('',(7.7,1.5,-12.7));
#529=DIRECTION('',(0.,1.,0.));
#530=DIRECTION('',(0.,0.,1.));
#531=AXIS2_PLACEMENT_3D('',#528,#529,#530);
#532=PLANE('',#531);
#533=ORIENTED_EDGE('',*,*,#452,.T.);
#534=EDGE_LOOP('',(#533));
#535=FACE_BOUND('',#534,.T.);
#536=ADVANCED_FACE('F304',(#535),#532,.T.);
#537=CARTESIAN_POINT('',(5.2,1.5,-12.7));
#538=DIRECTION('',(0.,1.,0.));
#539=DIRECTION('',(0.,0.,1.));
#540=AXIS2_PLACEMENT_3D('',#537,#538,#539);
#541=CYLINDRICAL_SURFACE('',#540,0.75);
#542=CARTESIAN_POINT('',(5.2,1.5,-12.7));
#543=DIRECTION('',(0.,1.,0.));
#544=DIRECTION('',(0.,0.,1.));
#545=AXIS2_PLACEMENT_3D('',#542,#543,#544);
#546=CIRCLE('',#545,0.75);
#547=CARTESIAN_POINT('',(5.2,1.5,-11.95));
#548=VERTEX_POINT('',#547);
#549=EDGE_CURVE('E118',#548,#548,#546,.T.);
#550=CARTESIAN_POINT('',(5.2,1.5,-11.95));
#551=CARTESIAN_POINT('',(5.2,1.57291666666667,-11.95));
#552=CARTESIAN_POINT('',(5.2,1.64583333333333,-11.95));
#553=CARTESIAN_POINT('',(5.2,1.79166666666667,-11.95));
#554=CARTESIAN_POINT('',(5.2,1.86458333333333,-11.95));
#555=CARTESIAN_POINT('',(5.2,2.01041666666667,-11.95));
#556=CARTESIAN_POINT('',(5.2,2.08333333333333,-11.95));
#557=CARTESIAN_POINT('',(5.2,2.22916666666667,-11.95));
#558=CARTESIAN_POINT('',(5.2,2.30208333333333,-11.95));
#559=CARTESIAN_POINT('',(5.2,2.44791666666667,-11.95));
#560=CARTESIAN_POINT('',(5.2,2.52083333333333,-11.95));
#561=CARTESIAN_POINT('',(5.2,2.66666666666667,-11.95));
#562=CARTESIAN_POINT('',(5.2,2.73958333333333,-11.95));
#563=CARTESIAN_POINT('',(5.2,2.88541666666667,-11.95));
#564=CARTESIAN_POINT('',(5.2,2.95833333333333,-11.95));
#565=CARTESIAN_POINT('',(5.2,3.10416666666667,-11.95));
#566=CARTESIAN_POINT('',(5.2,3.17708333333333,-11.95));
#567=CARTESIAN_POINT('',(5.2,3.32291666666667,-11.95));
#568=CARTESIAN_POINT('',(5.2,3.39583333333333,-11.95));
#569=CARTESIAN_POINT('',(5.2,3.54166666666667,-11.95));
#570=CARTESIAN_POINT('',(5.2,3.61458333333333,-11.95));
#571=CARTESIAN_POINT('',(5.2,3.76041666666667,-11.95));
#572=CARTESIAN_POINT('',(5.2,3.83333333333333,-11.95));
#573=CARTESIAN_POINT('',(5.2,3.97916666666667,-11.95));
#574=CARTESIAN_POINT('',(5.2,4.05208333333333,-11.95));
#575=CARTESIAN_POINT('',(5.2,4.19791666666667,-11.95));
#576=CARTESIAN_POINT('',(5.2,4.27083333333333,-11.95));
#577=CARTESIAN_POINT('',(5.2,4.41666666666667,-11.95));
#578=CARTESIAN_POINT('',(5.2,4.48958333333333,-11.95));
#579=CARTESIAN_POINT('',(5.2,4.63541666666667,-11.95));
#580=CARTESIAN_POINT('',(5.2,4.70833333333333,-11.95));
#581=CARTESIAN_POINT('',(5.2,4.85416666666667,-11.95));
#582=CARTESIAN_POINT('',(5.2,4.92708333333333,-11.95));
#583=CARTESIAN_POINT('',(5.2,5.07291666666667,-11.95));
#584=CARTESIAN_POINT('',(5.2,5.14583333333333,-11.95));
#585=CARTESIAN_POINT('',(5.2,5.29166666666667,-11.95));
#586=CARTESIAN_POINT('',(5.2,5.36458333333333,-11.95));
#587=CARTESIAN_POINT('',(5.2,5.51041666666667,-11.95));
#588=CARTESIAN_POINT('',(5.2,5.58333333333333,-11.95));
#589=CARTESIAN_POINT('',(5.2,5.72916666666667,-11.95));
#590=CARTESIAN_POINT('',(5.2,5.80208333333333,-11.95));
#591=CARTESIAN_POINT('',(5.2,5.94791666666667,-11.95));
#592=CARTESIAN_POINT('',(5.2,6.02083333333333,-11.95));
#593=CARTESIAN_POINT('',(5.2,6.16666666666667,-11.95));
#594=CARTESIAN_POINT('',(5.2,6.23958333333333,-11.95));
#595=CARTESIAN_POINT('',(5.2,6.38541666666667,-11.95));
#596=CARTESIAN_POINT('',(5.2,6.45833333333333,-11.95));
#597=CARTESIAN_POINT('',(5.2,6.60416666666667,-11.95));
#598=CARTESIAN_POINT('',(5.2,6.67708333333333,-11.95));
#599=CARTESIAN_POINT('',(5.2,6.82291666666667,-11.95));
#600=CARTESIAN_POINT('',(5.2,6.89583333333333,-11.95));
#601=CARTESIAN_POINT('',(5.2,7.04166666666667,-11.95));
#602=CARTESIAN_POINT('',(5.2,7.11458333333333,-11.95));
#603=CARTESIAN_POINT('',(5.2,7.26041666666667,-11.95));
#604=CARTESIAN_POINT('',(5.2,7.33333333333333,-11.95));
#605=CARTESIAN_POINT('',(5.2,7.47916666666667,-11.95));
#606=CARTESIAN_POINT('',(5.2,7.55208333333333,-11.95));
#607=CARTESIAN_POINT('',(5.2,7.69791666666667,-11.95));
#608=CARTESIAN_POINT('',(5.2,7.77083333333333,-11.95));
#609=CARTESIAN_POINT('',(5.2,7.91666666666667,-11.95));
#610=CARTESIAN_POINT('',(5.2,7.98958333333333,-11.95));
#611=CARTESIAN_POINT('',(5.2,8.13541666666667,-11.95));
#612=CARTESIAN_POINT('',(5.2,8.20833333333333,-11.95));
#613=CARTESIAN_POINT('',(5.2,8.35416666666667,-11.95));
#614=CARTESIAN_POINT('',(5.2,8.42708333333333,-11.95));
#615=CARTESIAN_POINT('',(5.2,8.5,-11.95));
#616=B_SPLINE_CURVE_WITH_KNOTS('',3,(#550,#551,#552,#553,#554,#555,#556,#557,#558,#559,#560,
#561,#562,#563,#564,#565,#566,#567,#568,#569,#570,#571,#572,#573,#574,#575,#576,#577,#578,#579,
#580,#581,#582,#583,#584,#585,#586,#587,#588,#589,#590,#591,#592,#593,#594,#595,#596,#597,#598,
#599,#600,#601,#602,#603,#604,#605,#606,#607,#608,#609,#610,#611,#612,#613,#614,#615),
.UNSPECIFIED.,.F.,.F.,(4,2,2,2,2,2,2,2,2,2,2,2,2,2,2,2,2,2,2,2,2,2,2,2,2,2,2,2,2,2,2,2,4),(0.,
0.21875,0.4375,0.65625,0.875,1.09375,1.3125,1.53125,1.75,1.96875,2.1875,2.40625,2.625,2.84375,
3.0625,3.28125,3.5,3.71875,3.9375,4.15625,4.375,4.59375,4.8125,5.03125,5.25,5.46875,5.6875,
5.90625,6.125,6.34375,6.5625,6.78125,7.),.UNSPECIFIED.);
#617=EDGE_CURVE('BSEAM313',#548,#297,#616,.T.);
#618=ORIENTED_EDGE('',*,*,#549,.F.);
#619=ORIENTED_EDGE('',*,*,#298,.T.);
#620=ORIENTED_EDGE('',*,*,#617,.T.);
#621=ORIENTED_EDGE('',*,*,#617,.F.);
#622=EDGE_LOOP('',(#618,#620,#619,#621));
#623=FACE_BOUND('',#622,.T.);
#624=ADVANCED_FACE('F313',(#623),#541,.F.);
#625=CARTESIAN_POINT('',(5.2,1.5,-12.7));
#626=DIRECTION('',(0.,1.,0.));
#627=DIRECTION('',(0.,0.,1.));
#628=AXIS2_PLACEMENT_3D('',#625,#626,#627);
#629=PLANE('',#628);
#630=ORIENTED_EDGE('',*,*,#549,.T.);
#631=EDGE_LOOP('',(#630));
#632=FACE_BOUND('',#631,.T.);
#633=ADVANCED_FACE('F322',(#632),#629,.T.);
#634=CARTESIAN_POINT('',(2.7,1.5,-12.7));
#635=DIRECTION('',(0.,1.,0.));
#636=DIRECTION('',(0.,0.,1.));
#637=AXIS2_PLACEMENT_3D('',#634,#635,#636);
#638=CYLINDRICAL_SURFACE('',#637,0.75);
#639=CARTESIAN_POINT('',(2.7,1.5,-12.7));
#640=DIRECTION('',(0.,1.,0.));
#641=DIRECTION('',(0.,0.,1.));
#642=AXIS2_PLACEMENT_3D('',#639,#640,#641);
#643=CIRCLE('',#642,0.75);
#644=CARTESIAN_POINT('',(2.7,1.5,-11.9499999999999));
#645=VERTEX_POINT('',#644);
#646=EDGE_CURVE('E124',#645,#645,#643,.T.);
#647=CARTESIAN_POINT('',(2.7,1.5,-11.9499999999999));
#648=CARTESIAN_POINT('',(2.7,1.57291666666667,-11.9499999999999));
#649=CARTESIAN_POINT('',(2.7,1.64583333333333,-11.9499999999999));
#650=CARTESIAN_POINT('',(2.7,1.79166666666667,-11.9499999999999));
#651=CARTESIAN_POINT('',(2.7,1.86458333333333,-11.9499999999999));
#652=CARTESIAN_POINT('',(2.7,2.01041666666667,-11.9499999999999));
#653=CARTESIAN_POINT('',(2.7,2.08333333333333,-11.9499999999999));
#654=CARTESIAN_POINT('',(2.7,2.22916666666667,-11.9499999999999));
#655=CARTESIAN_POINT('',(2.7,2.30208333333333,-11.9499999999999));
#656=CARTESIAN_POINT('',(2.7,2.44791666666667,-11.9499999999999));
#657=CARTESIAN_POINT('',(2.7,2.52083333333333,-11.9499999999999));
#658=CARTESIAN_POINT('',(2.7,2.66666666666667,-11.9499999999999));
#659=CARTESIAN_POINT('',(2.7,2.73958333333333,-11.9499999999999));
#660=CARTESIAN_POINT('',(2.7,2.88541666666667,-11.9499999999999));
#661=CARTESIAN_POINT('',(2.7,2.95833333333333,-11.9499999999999));
#662=CARTESIAN_POINT('',(2.7,3.10416666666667,-11.9499999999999));
#663=CARTESIAN_POINT('',(2.7,3.17708333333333,-11.9499999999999));
#664=CARTESIAN_POINT('',(2.7,3.32291666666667,-11.9499999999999));
#665=CARTESIAN_POINT('',(2.7,3.39583333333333,-11.9499999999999));
#666=CARTESIAN_POINT('',(2.7,3.54166666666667,-11.9499999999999));
#667=CARTESIAN_POINT('',(2.7,3.61458333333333,-11.9499999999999));
#668=CARTESIAN_POINT('',(2.7,3.76041666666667,-11.9499999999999));
#669=CARTESIAN_POINT('',(2.7,3.83333333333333,-11.9499999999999));
#670=CARTESIAN_POINT('',(2.7,3.97916666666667,-11.9499999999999));
#671=CARTESIAN_POINT('',(2.7,4.05208333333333,-11.9499999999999));
#672=CARTESIAN_POINT('',(2.7,4.19791666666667,-11.9499999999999));
#673=CARTESIAN_POINT('',(2.7,4.27083333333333,-11.9499999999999));
#674=CARTESIAN_POINT('',(2.7,4.41666666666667,-11.9499999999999));
#675=CARTESIAN_POINT('',(2.7,4.48958333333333,-11.9499999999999));
#676=CARTESIAN_POINT('',(2.7,4.63541666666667,-11.9499999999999));
#677=CARTESIAN_POINT('',(2.7,4.70833333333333,-11.9499999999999));
#678=CARTESIAN_POINT('',(2.7,4.85416666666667,-11.9499999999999));
#679=CARTESIAN_POINT('',(2.7,4.92708333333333,-11.9499999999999));
#680=CARTESIAN_POINT('',(2.7,5.07291666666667,-11.9499999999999));
#681=CARTESIAN_POINT('',(2.7,5.14583333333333,-11.9499999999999));
#682=CARTESIAN_POINT('',(2.7,5.29166666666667,-11.9499999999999));
#683=CARTESIAN_POINT('',(2.7,5.36458333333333,-11.9499999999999));
#684=CARTESIAN_POINT('',(2.7,5.51041666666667,-11.9499999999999));
#685=CARTESIAN_POINT('',(2.7,5.58333333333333,-11.9499999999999));
#686=CARTESIAN_POINT('',(2.7,5.72916666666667,-11.9499999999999));
#687=CARTESIAN_POINT('',(2.7,5.80208333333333,-11.9499999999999));
#688=CARTESIAN_POINT('',(2.7,5.94791666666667,-11.9499999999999));
#689=CARTESIAN_POINT('',(2.7,6.02083333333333,-11.9499999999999));
#690=CARTESIAN_POINT('',(2.7,6.16666666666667,-11.9499999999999));
#691=CARTESIAN_POINT('',(2.7,6.23958333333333,-11.9499999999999));
#692=CARTESIAN_POINT('',(2.7,6.38541666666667,-11.9499999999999));
#693=CARTESIAN_POINT('',(2.7,6.45833333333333,-11.9499999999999));
#694=CARTESIAN_POINT('',(2.7,6.60416666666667,-11.9499999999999));
#695=CARTESIAN_POINT('',(2.7,6.67708333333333,-11.9499999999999));
#696=CARTESIAN_POINT('',(2.7,6.82291666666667,-11.9499999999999));
#697=CARTESIAN_POINT('',(2.7,6.89583333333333,-11.9499999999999));
#698=CARTESIAN_POINT('',(2.7,7.04166666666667,-11.9499999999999));
#699=CARTESIAN_POINT('',(2.7,7.11458333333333,-11.9499999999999));
#700=CARTESIAN_POINT('',(2.7,7.26041666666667,-11.9499999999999));
#701=CARTESIAN_POINT('',(2.7,7.33333333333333,-11.9499999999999));
#702=CARTESIAN_POINT('',(2.7,7.47916666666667,-11.9499999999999));
#703=CARTESIAN_POINT('',(2.7,7.55208333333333,-11.9499999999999));
#704=CARTESIAN_POINT('',(2.7,7.69791666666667,-11.9499999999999));
#705=CARTESIAN_POINT('',(2.7,7.77083333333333,-11.9499999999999));
#706=CARTESIAN_POINT('',(2.7,7.91666666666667,-11.9499999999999));
#707=CARTESIAN_POINT('',(2.7,7.98958333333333,-11.9499999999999));
#708=CARTESIAN_POINT('',(2.7,8.13541666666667,-11.9499999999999));
#709=CARTESIAN_POINT('',(2.7,8.20833333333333,-11.9499999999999));
#710=CARTESIAN_POINT('',(2.7,8.35416666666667,-11.9499999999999));
#711=CARTESIAN_POINT('',(2.7,8.42708333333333,-11.9499999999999));
#712=CARTESIAN_POINT('',(2.7,8.5,-11.9499999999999));
#713=B_SPLINE_CURVE_WITH_KNOTS('',3,(#647,#648,#649,#650,#651,#652,#653,#654,#655,#656,#657,
#658,#659,#660,#661,#662,#663,#664,#665,#666,#667,#668,#669,#670,#671,#672,#673,#674,#675,#676,
#677,#678,#679,#680,#681,#682,#683,#684,#685,#686,#687,#688,#689,#690,#691,#692,#693,#694,#695,
#696,#697,#698,#699,#700,#701,#702,#703,#704,#705,#706,#707,#708,#709,#710,#711,#712),
.UNSPECIFIED.,.F.,.F.,(4,2,2,2,2,2,2,2,2,2,2,2,2,2,2,2,2,2,2,2,2,2,2,2,2,2,2,2,2,2,2,2,4),(0.,
0.21875,0.4375,0.65625,0.875,1.09375,1.3125,1.53125,1.75,1.96875,2.1875,2.40625,2.625,2.84375,
3.0625,3.28125,3.5,3.71875,3.9375,4.15625,4.375,4.59375,4.8125,5.03125,5.25,5.46875,5.6875,
5.90625,6.125,6.34375,6.5625,6.78125,7.),.UNSPECIFIED.);
#714=EDGE_CURVE('BSEAM331',#645,#286,#713,.T.);
#715=ORIENTED_EDGE('',*,*,#646,.F.);
#716=ORIENTED_EDGE('',*,*,#287,.T.);
#717=ORIENTED_EDGE('',*,*,#714,.T.);
#718=ORIENTED_EDGE('',*,*,#714,.F.);
#719=EDGE_LOOP('',(#715,#717,#716,#718));
#720=FACE_BOUND('',#719,.T.);
#721=ADVANCED_FACE('F331',(#720),#638,.F.);
#722=CARTESIAN_POINT('',(2.7,1.5,-12.7));
#723=DIRECTION('',(0.,1.,0.));
#724=DIRECTION('',(0.,0.,1.));
#725=AXIS2_PLACEMENT_3D('',#722,#723,#724);
#726=PLANE('',#725);
#727=ORIENTED_EDGE('',*,*,#646,.T.);
#728=EDGE_LOOP('',(#727));
#729=FACE_BOUND('',#728,.T.);
#730=ADVANCED_FACE('F340',(#729),#726,.T.);
#731=CARTESIAN_POINT('',(7.70000000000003,1.5,-10.2));
#732=DIRECTION('',(0.,1.,0.));
#733=DIRECTION('',(0.,0.,1.));
#734=AXIS2_PLACEMENT_3D('',#731,#732,#733);
#735=CYLINDRICAL_SURFACE('',#734,0.75);
#736=CARTESIAN_POINT('',(7.70000000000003,1.5,-10.2));
#737=DIRECTION('',(0.,1.,0.));
#738=DIRECTION('',(0.,0.,1.));
#739=AXIS2_PLACEMENT_3D('',#736,#737,#738);
#740=CIRCLE('',#739,0.75);
#741=CARTESIAN_POINT('',(7.70000000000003,1.5,-9.44999999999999));
#742=VERTEX_POINT('',#741);
#743=EDGE_CURVE('E130',#742,#742,#740,.T.);
#744=CARTESIAN_POINT('',(7.70000000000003,1.5,-9.44999999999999));
#745=CARTESIAN_POINT('',(7.70000000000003,1.57291666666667,-9.44999999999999));
#746=CARTESIAN_POINT('',(7.70000000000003,1.64583333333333,-9.44999999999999));
#747=CARTESIAN_POINT('',(7.70000000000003,1.79166666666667,-9.44999999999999));
#748=CARTESIAN_POINT('',(7.70000000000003,1.86458333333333,-9.44999999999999));
#749=CARTESIAN_POINT('',(7.70000000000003,2.01041666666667,-9.44999999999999));
#750=CARTESIAN_POINT('',(7.70000000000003,2.08333333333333,-9.44999999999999));
#751=CARTESIAN_POINT('',(7.70000000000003,2.22916666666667,-9.44999999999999));
#752=CARTESIAN_POINT('',(7.70000000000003,2.30208333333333,-9.44999999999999));
#753=CARTESIAN_POINT('',(7.70000000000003,2.44791666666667,-9.44999999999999));
#754=CARTESIAN_POINT('',(7.70000000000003,2.52083333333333,-9.44999999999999));
#755=CARTESIAN_POINT('',(7.70000000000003,2.66666666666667,-9.44999999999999));
#756=CARTESIAN_POINT('',(7.70000000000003,2.73958333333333,-9.44999999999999));
#757=CARTESIAN_POINT('',(7.70000000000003,2.88541666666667,-9.44999999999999));
#758=CARTESIAN_POINT('',(7.70000000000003,2.95833333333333,-9.44999999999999));
#759=CARTESIAN_POINT('',(7.70000000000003,3.10416666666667,-9.44999999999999));
#760=CARTESIAN_POINT('',(7.70000000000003,3.17708333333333,-9.44999999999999));
#761=CARTESIAN_POINT('',(7.70000000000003,3.32291666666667,-9.44999999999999));
#762=CARTESIAN_POINT('',(7.70000000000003,3.39583333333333,-9.44999999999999));
#763=CARTESIAN_POINT('',(7.70000000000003,3.54166666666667,-9.44999999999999));
#764=CARTESIAN_POINT('',(7.70000000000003,3.61458333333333,-9.44999999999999));
#765=CARTESIAN_POINT('',(7.70000000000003,3.76041666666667,-9.44999999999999));
#766=CARTESIAN_POINT('',(7.70000000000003,3.83333333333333,-9.44999999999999));
#767=CARTESIAN_POINT('',(7.70000000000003,3.97916666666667,-9.44999999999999));
#768=CARTESIAN_POINT('',(7.70000000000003,4.05208333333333,-9.44999999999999));
#769=CARTESIAN_POINT('',(7.70000000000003,4.19791666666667,-9.44999999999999));
#770=CARTESIAN_POINT('',(7.70000000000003,4.27083333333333,-9.44999999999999));
#771=CARTESIAN_POINT('',(7.70000000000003,4.41666666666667,-9.44999999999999));
#772=CARTESIAN_POINT('',(7.70000000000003,4.48958333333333,-9.44999999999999));
#773=CARTESIAN_POINT('',(7.70000000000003,4.63541666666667,-9.44999999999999));
#774=CARTESIAN_POINT('',(7.70000000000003,4.70833333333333,-9.44999999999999));
#775=CARTESIAN_POINT('',(7.70000000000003,4.85416666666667,-9.44999999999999));
#776=CARTESIAN_POINT('',(7.70000000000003,4.92708333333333,-9.44999999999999));
#777=CARTESIAN_POINT('',(7.70000000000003,5.07291666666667,-9.44999999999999));
#778=CARTESIAN_POINT('',(7.70000000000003,5.14583333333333,-9.44999999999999));
#779=CARTESIAN_POINT('',(7.70000000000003,5.29166666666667,-9.44999999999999));
#780=CARTESIAN_POINT('',(7.70000000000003,5.36458333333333,-9.44999999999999));
#781=CARTESIAN_POINT('',(7.70000000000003,5.51041666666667,-9.44999999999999));
#782=CARTESIAN_POINT('',(7.70000000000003,5.58333333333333,-9.44999999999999));
#783=CARTESIAN_POINT('',(7.70000000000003,5.72916666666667,-9.44999999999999));
#784=CARTESIAN_POINT('',(7.70000000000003,5.80208333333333,-9.44999999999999));
#785=CARTESIAN_POINT('',(7.70000000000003,5.94791666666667,-9.44999999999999));
#786=CARTESIAN_POINT('',(7.70000000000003,6.02083333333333,-9.44999999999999));
#787=CARTESIAN_POINT('',(7.70000000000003,6.16666666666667,-9.44999999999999));
#788=CARTESIAN_POINT('',(7.70000000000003,6.23958333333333,-9.44999999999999));
#789=CARTESIAN_POINT('',(7.70000000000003,6.38541666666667,-9.44999999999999));
#790=CARTESIAN_POINT('',(7.70000000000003,6.45833333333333,-9.44999999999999));
#791=CARTESIAN_POINT('',(7.70000000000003,6.60416666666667,-9.44999999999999));
#792=CARTESIAN_POINT('',(7.70000000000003,6.67708333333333,-9.44999999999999));
#793=CARTESIAN_POINT('',(7.70000000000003,6.82291666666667,-9.44999999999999));
#794=CARTESIAN_POINT('',(7.70000000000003,6.89583333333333,-9.44999999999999));
#795=CARTESIAN_POINT('',(7.70000000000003,7.04166666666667,-9.44999999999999));
#796=CARTESIAN_POINT('',(7.70000000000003,7.11458333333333,-9.44999999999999));
#797=CARTESIAN_POINT('',(7.70000000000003,7.26041666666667,-9.44999999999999));
#798=CARTESIAN_POINT('',(7.70000000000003,7.33333333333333,-9.44999999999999));
#799=CARTESIAN_POINT('',(7.70000000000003,7.47916666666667,-9.44999999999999));
#800=CARTESIAN_POINT('',(7.70000000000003,7.55208333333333,-9.44999999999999));
#801=CARTESIAN_POINT('',(7.70000000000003,7.69791666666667,-9.44999999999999));
#802=CARTESIAN_POINT('',(7.70000000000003,7.77083333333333,-9.44999999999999));
#803=CARTESIAN_POINT('',(7.70000000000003,7.91666666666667,-9.44999999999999));
#804=CARTESIAN_POINT('',(7.70000000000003,7.98958333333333,-9.44999999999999));
#805=CARTESIAN_POINT('',(7.70000000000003,8.13541666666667,-9.44999999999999));
#806=CARTESIAN_POINT('',(7.70000000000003,8.20833333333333,-9.44999999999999));
#807=CARTESIAN_POINT('',(7.70000000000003,8.35416666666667,-9.44999999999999));
#808=CARTESIAN_POINT('',(7.70000000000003,8.42708333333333,-9.44999999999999));
#809=CARTESIAN_POINT('',(7.70000000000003,8.5,-9.44999999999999));
#810=B_SPLINE_CURVE_WITH_KNOTS('',3,(#744,#745,#746,#747,#748,#749,#750,#751,#752,#753,#754,
#755,#756,#757,#758,#759,#760,#761,#762,#763,#764,#765,#766,#767,#768,#769,#770,#771,#772,#773,
#774,#775,#776,#777,#778,#779,#780,#781,#782,#783,#784,#785,#786,#787,#788,#789,#790,#791,#792,
#793,#794,#795,#796,#797,#798,#799,#800,#801,#802,#803,#804,#805,#806,#807,#808,#809),
.UNSPECIFIED.,.F.,.F.,(4,2,2,2,2,2,2,2,2,2,2,2,2,2,2,2,2,2,2,2,2,2,2,2,2,2,2,2,2,2,2,2,4),(0.,
0.21875,0.4375,0.65625,0.875,1.09375,1.3125,1.53125,1.75,1.96875,2.1875,2.40625,2.625,2.84375,
3.0625,3.28125,3.5,3.71875,3.9375,4.15625,4.375,4.59375,4.8125,5.03125,5.25,5.46875,5.6875,
5.90625,6.125,6.34375,6.5625,6.78125,7.),.UNSPECIFIED.);
#811=EDGE_CURVE('BSEAM349',#742,#275,#810,.T.);
#812=ORIENTED_EDGE('',*,*,#743,.F.);
#813=ORIENTED_EDGE('',*,*,#276,.T.);
#814=ORIENTED_EDGE('',*,*,#811,.T.);
#815=ORIENTED_EDGE('',*,*,#811,.F.);
#816=EDGE_LOOP('',(#812,#814,#813,#815));
#817=FACE_BOUND('',#816,.T.);
#818=ADVANCED_FACE('F349',(#817),#735,.F.);
#819=CARTESIAN_POINT('',(7.70000000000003,1.5,-10.2));
#820=DIRECTION('',(0.,1.,0.));
#821=DIRECTION('',(0.,0.,1.));
#822=AXIS2_PLACEMENT_3D('',#819,#820,#821);
#823=PLANE('',#822);
#824=ORIENTED_EDGE('',*,*,#743,.T.);
#825=EDGE_LOOP('',(#824));
#826=FACE_BOUND('',#825,.T.);
#827=ADVANCED_FACE('F358',(#826),#823,.T.);
#828=CARTESIAN_POINT('',(5.20000000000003,1.5,-10.2));
#829=DIRECTION('',(0.,1.,0.));
#830=DIRECTION('',(0.,0.,1.));
#831=AXIS2_PLACEMENT_3D('',#828,#829,#830);
#832=CYLINDRICAL_SURFACE('',#831,0.75);
#833=CARTESIAN_POINT('',(5.20000000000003,1.5,-10.2));
#834=DIRECTION('',(0.,1.,0.));
#835=DIRECTION('',(0.,0.,1.));
#836=AXIS2_PLACEMENT_3D('',#833,#834,#835);
#837=CIRCLE('',#836,0.75);
#838=CARTESIAN_POINT('',(5.20000000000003,1.5,-9.44999999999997));
#839=VERTEX_POINT('',#838);
#840=EDGE_CURVE('E136',#839,#839,#837,.T.);
#841=CARTESIAN_POINT('',(5.20000000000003,1.5,-9.44999999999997));
#842=CARTESIAN_POINT('',(5.20000000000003,1.57291666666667,-9.44999999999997));
#843=CARTESIAN_POINT('',(5.20000000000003,1.64583333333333,-9.44999999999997));
#844=CARTESIAN_POINT('',(5.20000000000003,1.79166666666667,-9.44999999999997));
#845=CARTESIAN_POINT('',(5.20000000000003,1.86458333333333,-9.44999999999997));
#846=CARTESIAN_POINT('',(5.20000000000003,2.01041666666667,-9.44999999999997));
#847=CARTESIAN_POINT('',(5.20000000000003,2.08333333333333,-9.44999999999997));
#848=CARTESIAN_POINT('',(5.20000000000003,2.22916666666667,-9.44999999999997));
#849=CARTESIAN_POINT('',(5.20000000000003,2.30208333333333,-9.44999999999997));
#850=CARTESIAN_POINT('',(5.20000000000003,2.44791666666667,-9.44999999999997));
#851=CARTESIAN_POINT('',(5.20000000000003,2.52083333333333,-9.44999999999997));
#852=CARTESIAN_POINT('',(5.20000000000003,2.66666666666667,-9.44999999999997));
#853=CARTESIAN_POINT('',(5.20000000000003,2.73958333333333,-9.44999999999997));
#854=CARTESIAN_POINT('',(5.20000000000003,2.88541666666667,-9.44999999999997));
#855=CARTESIAN_POINT('',(5.20000000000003,2.95833333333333,-9.44999999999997));
#856=CARTESIAN_POINT('',(5.20000000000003,3.10416666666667,-9.44999999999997));
#857=CARTESIAN_POINT('',(5.20000000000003,3.17708333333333,-9.44999999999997));
#858=CARTESIAN_POINT('',(5.20000000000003,3.32291666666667,-9.44999999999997));
#859=CARTESIAN_POINT('',(5.20000000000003,3.39583333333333,-9.44999999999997));
#860=CARTESIAN_POINT('',(5.20000000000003,3.54166666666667,-9.44999999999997));
#861=CARTESIAN_POINT('',(5.20000000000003,3.61458333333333,-9.44999999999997));
#862=CARTESIAN_POINT('',(5.20000000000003,3.76041666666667,-9.44999999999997));
#863=CARTESIAN_POINT('',(5.20000000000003,3.83333333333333,-9.44999999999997));
#864=CARTESIAN_POINT('',(5.20000000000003,3.97916666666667,-9.44999999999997));
#865=CARTESIAN_POINT('',(5.20000000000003,4.05208333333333,-9.44999999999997));
#866=CARTESIAN_POINT('',(5.20000000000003,4.19791666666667,-9.44999999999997));
#867=CARTESIAN_POINT('',(5.20000000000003,4.27083333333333,-9.44999999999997));
#868=CARTESIAN_POINT('',(5.20000000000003,4.41666666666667,-9.44999999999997));
#869=CARTESIAN_POINT('',(5.20000000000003,4.48958333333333,-9.44999999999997));
#870=CARTESIAN_POINT('',(5.20000000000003,4.63541666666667,-9.44999999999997));
#871=CARTESIAN_POINT('',(5.20000000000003,4.70833333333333,-9.44999999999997));
#872=CARTESIAN_POINT('',(5.20000000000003,4.85416666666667,-9.44999999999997));
#873=CARTESIAN_POINT('',(5.20000000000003,4.92708333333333,-9.44999999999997));
#874=CARTESIAN_POINT('',(5.20000000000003,5.07291666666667,-9.44999999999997));
#875=CARTESIAN_POINT('',(5.20000000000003,5.14583333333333,-9.44999999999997));
#876=CARTESIAN_POINT('',(5.20000000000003,5.29166666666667,-9.44999999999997));
#877=CARTESIAN_POINT('',(5.20000000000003,5.36458333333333,-9.44999999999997));
#878=CARTESIAN_POINT('',(5.20000000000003,5.51041666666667,-9.44999999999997));
#879=CARTESIAN_POINT('',(5.20000000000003,5.58333333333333,-9.44999999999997));
#880=CARTESIAN_POINT('',(5.20000000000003,5.72916666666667,-9.44999999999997));
#881=CARTESIAN_POINT('',(5.20000000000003,5.80208333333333,-9.44999999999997));
#882=CARTESIAN_POINT('',(5.20000000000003,5.94791666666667,-9.44999999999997));
#883=CARTESIAN_POINT('',(5.20000000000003,6.02083333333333,-9.44999999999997));
#884=CARTESIAN_POINT('',(5.20000000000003,6.16666666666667,-9.44999999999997));
#885=CARTESIAN_POINT('',(5.20000000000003,6.23958333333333,-9.44999999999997));
#886=CARTESIAN_POINT('',(5.20000000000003,6.38541666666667,-9.44999999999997));
#887=CARTESIAN_POINT('',(5.20000000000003,6.45833333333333,-9.44999999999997));
#888=CARTESIAN_POINT('',(5.20000000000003,6.60416666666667,-9.44999999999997));
#889=CARTESIAN_POINT('',(5.20000000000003,6.67708333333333,-9.44999999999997));
#890=CARTESIAN_POINT('',(5.20000000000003,6.82291666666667,-9.44999999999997));
#891=CARTESIAN_POINT('',(5.20000000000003,6.89583333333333,-9.44999999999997));
#892=CARTESIAN_POINT('',(5.20000000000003,7.04166666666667,-9.44999999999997));
#893=CARTESIAN_POINT('',(5.20000000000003,7.11458333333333,-9.44999999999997));
#894=CARTESIAN_POINT('',(5.20000000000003,7.26041666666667,-9.44999999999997));
#895=CARTESIAN_POINT('',(5.20000000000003,7.33333333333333,-9.44999999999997));
#896=CARTESIAN_POINT('',(5.20000000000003,7.47916666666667,-9.44999999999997));
#897=CARTESIAN_POINT('',(5.20000000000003,7.55208333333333,-9.44999999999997));
#898=CARTESIAN_POINT('',(5.20000000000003,7.69791666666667,-9.44999999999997));
#899=CARTESIAN_POINT('',(5.20000000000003,7.77083333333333,-9.44999999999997));
#900=CARTESIAN_POINT('',(5.20000000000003,7.91666666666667,-9.44999999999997));
#901=CARTESIAN_POINT('',(5.20000000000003,7.98958333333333,-9.44999999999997));
#902=CARTESIAN_POINT('',(5.20000000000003,8.13541666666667,-9.44999999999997));
#903=CARTESIAN_POINT('',(5.20000000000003,8.20833333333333,-9.44999999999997));
#904=CARTESIAN_POINT('',(5.20000000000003,8.35416666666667,-9.44999999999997));
#905=CARTESIAN_POINT('',(5.20000000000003,8.42708333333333,-9.44999999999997));
#906=CARTESIAN_POINT('',(5.20000000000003,8.5,-9.44999999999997));
#907=B_SPLINE_CURVE_WITH_KNOTS('',3,(#841,#842,#843,#844,#845,#846,#847,#848,#849,#850,#851,
#852,#853,#854,#855,#856,#857,#858,#859,#860,#861,#862,#863,#864,#865,#866,#867,#868,#869,#870,
#871,#872,#873,#874,#875,#876,#877,#878,#879,#880,#881,#882,#883,#884,#885,#886,#887,#888,#889,
#890,#891,#892,#893,#894,#895,#896,#897,#898,#899,#900,#901,#902,#903,#904,#905,#906),
.UNSPECIFIED.,.F.,.F.,(4,2,2,2,2,2,2,2,2,2,2,2,2,2,2,2,2,2,2,2,2,2,2,2,2,2,2,2,2,2,2,2,4),(0.,
0.21875,0.4375,0.65625,0.875,1.09375,1.3125,1.53125,1.75,1.96875,2.1875,2.40625,2.625,2.84375,
3.0625,3.28125,3.5,3.71875,3.9375,4.15625,4.375,4.59375,4.8125,5.03125,5.25,5.46875,5.6875,
5.90625,6.125,6.34375,6.5625,6.78125,7.),.UNSPECIFIED.);
#908=EDGE_CURVE('BSEAM367',#839,#264,#907,.T.);
#909=ORIENTED_EDGE('',*,*,#840,.F.);
#910=ORIENTED_EDGE('',*,*,#265,.T.);
#911=ORIENTED_EDGE('',*,*,#908,.T.);
#912=ORIENTED_EDGE('',*,*,#908,.F.);
#913=EDGE_LOOP('',(#909,#911,#910,#912));
#914=FACE_BOUND('',#913,.T.);
#915=ADVANCED_FACE('F367',(#914),#832,.F.);
#916=CARTESIAN_POINT('',(5.20000000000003,1.5,-10.2));
#917=DIRECTION('',(0.,1.,0.));
#918=DIRECTION('',(0.,0.,1.));
#919=AXIS2_PLACEMENT_3D('',#916,#917,#918);
#920=PLANE('',#919);
#921=ORIENTED_EDGE('',*,*,#840,.T.);
#922=EDGE_LOOP('',(#921));
#923=FACE_BOUND('',#922,.T.);
#924=ADVANCED_FACE('F376',(#923),#920,.T.);
#925=CARTESIAN_POINT('',(2.70000000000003,1.5,-10.1999999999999));
#926=DIRECTION('',(0.,1.,0.));
#927=DIRECTION('',(0.,0.,1.));
#928=AXIS2_PLACEMENT_3D('',#925,#926,#927);
#929=CYLINDRICAL_SURFACE('',#928,0.75);
#930=CARTESIAN_POINT('',(2.70000000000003,1.5,-10.1999999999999));
#931=DIRECTION('',(0.,1.,0.));
#932=DIRECTION('',(0.,0.,1.));
#933=AXIS2_PLACEMENT_3D('',#930,#931,#932);
#934=CIRCLE('',#933,0.75);
#935=CARTESIAN_POINT('',(2.70000000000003,1.5,-9.44999999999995));
#936=VERTEX_POINT('',#935);
#937=EDGE_CURVE('E142',#936,#936,#934,.T.);
#938=CARTESIAN_POINT('',(2.70000000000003,1.5,-9.44999999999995));
#939=CARTESIAN_POINT('',(2.70000000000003,1.57291666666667,-9.44999999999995));
#940=CARTESIAN_POINT('',(2.70000000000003,1.64583333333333,-9.44999999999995));
#941=CARTESIAN_POINT('',(2.70000000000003,1.79166666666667,-9.44999999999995));
#942=CARTESIAN_POINT('',(2.70000000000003,1.86458333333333,-9.44999999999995));
#943=CARTESIAN_POINT('',(2.70000000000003,2.01041666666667,-9.44999999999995));
#944=CARTESIAN_POINT('',(2.70000000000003,2.08333333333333,-9.44999999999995));
#945=CARTESIAN_POINT('',(2.70000000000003,2.22916666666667,-9.44999999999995));
#946=CARTESIAN_POINT('',(2.70000000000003,2.30208333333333,-9.44999999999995));
#947=CARTESIAN_POINT('',(2.70000000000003,2.44791666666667,-9.44999999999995));
#948=CARTESIAN_POINT('',(2.70000000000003,2.52083333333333,-9.44999999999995));
#949=CARTESIAN_POINT('',(2.70000000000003,2.66666666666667,-9.44999999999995));
#950=CARTESIAN_POINT('',(2.70000000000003,2.73958333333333,-9.44999999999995));
#951=CARTESIAN_POINT('',(2.70000000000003,2.88541666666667,-9.44999999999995));
#952=CARTESIAN_POINT('',(2.70000000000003,2.95833333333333,-9.44999999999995));
#953=CARTESIAN_POINT('',(2.70000000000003,3.10416666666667,-9.44999999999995));
#954=CARTESIAN_POINT('',(2.70000000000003,3.17708333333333,-9.44999999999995));
#955=CARTESIAN_POINT('',(2.70000000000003,3.32291666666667,-9.44999999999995));
#956=CARTESIAN_POINT('',(2.70000000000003,3.39583333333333,-9.44999999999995));
#957=CARTESIAN_POINT('',(2.70000000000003,3.54166666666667,-9.44999999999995));
#958=CARTESIAN_POINT('',(2.70000000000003,3.61458333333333,-9.44999999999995));
#959=CARTESIAN_POINT('',(2.70000000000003,3.76041666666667,-9.44999999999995));
#960=CARTESIAN_POINT('',(2.70000000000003,3.83333333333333,-9.44999999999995));
#961=CARTESIAN_POINT('',(2.70000000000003,3.97916666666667,-9.44999999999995));
#962=CARTESIAN_POINT('',(2.70000000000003,4.05208333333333,-9.44999999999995));
#963=CARTESIAN_POINT('',(2.70000000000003,4.19791666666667,-9.44999999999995));
#964=CARTESIAN_POINT('',(2.70000000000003,4.27083333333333,-9.44999999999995));
#965=CARTESIAN_POINT('',(2.70000000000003,4.41666666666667,-9.44999999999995));
#966=CARTESIAN_POINT('',(2.70000000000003,4.48958333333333,-9.44999999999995));
#967=CARTESIAN_POINT('',(2.70000000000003,4.63541666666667,-9.44999999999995));
#968=CARTESIAN_POINT('',(2.70000000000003,4.70833333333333,-9.44999999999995));
#969=CARTESIAN_POINT('',(2.70000000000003,4.85416666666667,-9.44999999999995));
#970=CARTESIAN_POINT('',(2.70000000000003,4.92708333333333,-9.44999999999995));
#971=CARTESIAN_POINT('',(2.70000000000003,5.07291666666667,-9.44999999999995));
#972=CARTESIAN_POINT('',(2.70000000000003,5.14583333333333,-9.44999999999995));
#973=CARTESIAN_POINT('',(2.70000000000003,5.29166666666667,-9.44999999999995));
#974=CARTESIAN_POINT('',(2.70000000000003,5.36458333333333,-9.44999999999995));
#975=CARTESIAN_POINT('',(2.70000000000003,5.51041666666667,-9.44999999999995));
#976=CARTESIAN_POINT('',(2.70000000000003,5.58333333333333,-9.44999999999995));
#977=CARTESIAN_POINT('',(2.70000000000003,5.72916666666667,-9.44999999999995));
#978=CARTESIAN_POINT('',(2.70000000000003,5.80208333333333,-9.44999999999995));
#979=CARTESIAN_POINT('',(2.70000000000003,5.94791666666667,-9.44999999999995));
#980=CARTESIAN_POINT('',(2.70000000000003,6.02083333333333,-9.44999999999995));
#981=CARTESIAN_POINT('',(2.70000000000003,6.16666666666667,-9.44999999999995));
#982=CARTESIAN_POINT('',(2.70000000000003,6.23958333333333,-9.44999999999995));
#983=CARTESIAN_POINT('',(2.70000000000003,6.38541666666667,-9.44999999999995));
#984=CARTESIAN_POINT('',(2.70000000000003,6.45833333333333,-9.44999999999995));
#985=CARTESIAN_POINT('',(2.70000000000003,6.60416666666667,-9.44999999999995));
#986=CARTESIAN_POINT('',(2.70000000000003,6.67708333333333,-9.44999999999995));
#987=CARTESIAN_POINT('',(2.70000000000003,6.82291666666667,-9.44999999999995));
#988=CARTESIAN_POINT('',(2.70000000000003,6.89583333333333,-9.44999999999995));
#989=CARTESIAN_POINT('',(2.70000000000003,7.04166666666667,-9.44999999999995));
#990=CARTESIAN_POINT('',(2.70000000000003,7.11458333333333,-9.44999999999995));
#991=CARTESIAN_POINT('',(2.70000000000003,7.26041666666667,-9.44999999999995));
#992=CARTESIAN_POINT('',(2.70000000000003,7.33333333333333,-9.44999999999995));
#993=CARTESIAN_POINT('',(2.70000000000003,7.47916666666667,-9.44999999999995));
#994=CARTESIAN_POINT('',(2.70000000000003,7.55208333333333,-9.44999999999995));
#995=CARTESIAN_POINT('',(2.70000000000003,7.69791666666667,-9.44999999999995));
#996=CARTESIAN_POINT('',(2.70000000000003,7.77083333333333,-9.44999999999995));
#997=CARTESIAN_POINT('',(2.70000000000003,7.91666666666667,-9.44999999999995));
#998=CARTESIAN_POINT('',(2.70000000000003,7.98958333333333,-9.44999999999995));
#999=CARTESIAN_POINT('',(2.70000000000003,8.13541666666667,-9.44999999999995));
#1000=CARTESIAN_POINT('',(2.70000000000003,8.20833333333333,-9.44999999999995));
#1001=CARTESIAN_POINT('',(2.70000000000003,8.35416666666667,-9.44999999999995));
#1002=CARTESIAN_POINT('',(2.70000000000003,8.42708333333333,-9.44999999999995));
#1003=CARTESIAN_POINT('',(2.70000000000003,8.5,-9.44999999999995));
#1004=B_SPLINE_CURVE_WITH_KNOTS('',3,(#938,#939,#940,#941,#942,#943,#944,#945,#946,#947,#948,
#949,#950,#951,#952,#953,#954,#955,#956,#957,#958,#959,#960,#961,#962,#963,#964,#965,#966,#967,
#968,#969,#970,#971,#972,#973,#974,#975,#976,#977,#978,#979,#980,#981,#982,#983,#984,#985,#986,
#987,#988,#989,#990,#991,#992,#993,#994,#995,#996,#997,#998,#999,#1000,#1001,#1002,#1003),
.UNSPECIFIED.,.F.,.F.,(4,2,2,2,2,2,2,2,2,2,2,2,2,2,2,2,2,2,2,2,2,2,2,2,2,2,2,2,2,2,2,2,4),(0.,
0.21875,0.4375,0.65625,0.875,1.09375,1.3125,1.53125,1.75,1.96875,2.1875,2.40625,2.625,2.84375,
3.0625,3.28125,3.5,3.71875,3.9375,4.15625,4.375,4.59375,4.8125,5.03125,5.25,5.46875,5.6875,
5.90625,6.125,6.34375,6.5625,6.78125,7.),.UNSPECIFIED.);
#1005=EDGE_CURVE('BSEAM385',#936,#253,#1004,.T.);
#1006=ORIENTED_EDGE('',*,*,#937,.F.);
#1007=ORIENTED_EDGE('',*,*,#254,.T.);
#1008=ORIENTED_EDGE('',*,*,#1005,.T.);
#1009=ORIENTED_EDGE('',*,*,#1005,.F.);
#1010=EDGE_LOOP('',(#1006,#1008,#1007,#1009));
#1011=FACE_BOUND('',#1010,.T.);
#1012=ADVANCED_FACE('F385',(#1011),#929,.F.);
#1013=CARTESIAN_POINT('',(2.70000000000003,1.5,-10.1999999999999));
#1014=DIRECTION('',(0.,1.,0.));
#1015=DIRECTION('',(0.,0.,1.));
#1016=AXIS2_PLACEMENT_3D('',#1013,#1014,#1015);
#1017=PLANE('',#1016);
#1018=ORIENTED_EDGE('',*,*,#937,.T.);
#1019=EDGE_LOOP('',(#1018));
#1020=FACE_BOUND('',#1019,.T.);
#1021=ADVANCED_FACE('F394',(#1020),#1017,.T.);
#1022=CARTESIAN_POINT('',(7.70000000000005,1.5,-7.69999999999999));
#1023=DIRECTION('',(0.,1.,0.));
#1024=DIRECTION('',(0.,0.,1.));
#1025=AXIS2_PLACEMENT_3D('',#1022,#1023,#1024);
#1026=CYLINDRICAL_SURFACE('',#1025,0.749999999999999);
#1027=CARTESIAN_POINT('',(7.70000000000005,1.5,-7.69999999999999));
#1028=DIRECTION('',(0.,1.,0.));
#1029=DIRECTION('',(0.,0.,1.));
#1030=AXIS2_PLACEMENT_3D('',#1027,#1028,#1029);
#1031=CIRCLE('',#1030,0.749999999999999);
#1032=CARTESIAN_POINT('',(7.70000000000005,1.5,-6.94999999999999));
#1033=VERTEX_POINT('',#1032);
#1034=EDGE_CURVE('E148',#1033,#1033,#1031,.T.);
#1035=CARTESIAN_POINT('',(7.70000000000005,1.5,-6.94999999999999));
#1036=CARTESIAN_POINT('',(7.70000000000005,1.57291666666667,-6.94999999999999));
#1037=CARTESIAN_POINT('',(7.70000000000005,1.64583333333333,-6.94999999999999));
#1038=CARTESIAN_POINT('',(7.70000000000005,1.79166666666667,-6.94999999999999));
#1039=CARTESIAN_POINT('',(7.70000000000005,1.86458333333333,-6.94999999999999));
#1040=CARTESIAN_POINT('',(7.70000000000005,2.01041666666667,-6.94999999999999));
#1041=CARTESIAN_POINT('',(7.70000000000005,2.08333333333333,-6.94999999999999));
#1042=CARTESIAN_POINT('',(7.70000000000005,2.22916666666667,-6.94999999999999));
#1043=CARTESIAN_POINT('',(7.70000000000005,2.30208333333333,-6.94999999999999));
#1044=CARTESIAN_POINT('',(7.70000000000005,2.44791666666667,-6.94999999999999));
#1045=CARTESIAN_POINT('',(7.70000000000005,2.52083333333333,-6.94999999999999));
#1046=CARTESIAN_POINT('',(7.70000000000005,2.66666666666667,-6.94999999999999));
#1047=CARTESIAN_POINT('',(7.70000000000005,2.73958333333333,-6.94999999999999));
#1048=CARTESIAN_POINT('',(7.70000000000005,2.88541666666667,-6.94999999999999));
#1049=CARTESIAN_POINT('',(7.70000000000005,2.95833333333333,-6.94999999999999));
#1050=CARTESIAN_POINT('',(7.70000000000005,3.10416666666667,-6.94999999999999));
#1051=CARTESIAN_POINT('',(7.70000000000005,3.17708333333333,-6.94999999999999));
#1052=CARTESIAN_POINT('',(7.70000000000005,3.32291666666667,-6.94999999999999));
#1053=CARTESIAN_POINT('',(7.70000000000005,3.39583333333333,-6.94999999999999));
#1054=CARTESIAN_POINT('',(7.70000000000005,3.54166666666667,-6.94999999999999));
#1055=CARTESIAN_POINT('',(7.70000000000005,3.61458333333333,-6.94999999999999));
#1056=CARTESIAN_POINT('',(7.70000000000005,3.76041666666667,-6.94999999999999));
#1057=CARTESIAN_POINT('',(7.70000000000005,3.83333333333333,-6.94999999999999));
#1058=CARTESIAN_POINT('',(7.70000000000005,3.97916666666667,-6.94999999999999));
#1059=CARTESIAN_POINT('',(7.70000000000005,4.05208333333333,-6.94999999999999));
#1060=CARTESIAN_POINT('',(7.70000000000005,4.19791666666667,-6.94999999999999));
#1061=CARTESIAN_POINT('',(7.70000000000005,4.27083333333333,-6.94999999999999));
#1062=CARTESIAN_POINT('',(7.70000000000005,4.41666666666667,-6.94999999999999));
#1063=CARTESIAN_POINT('',(7.70000000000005,4.48958333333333,-6.94999999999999));
#1064=CARTESIAN_POINT('',(7.70000000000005,4.63541666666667,-6.94999999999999));
#1065=CARTESIAN_POINT('',(7.70000000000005,4.70833333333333,-6.94999999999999));
#1066=CARTESIAN_POINT('',(7.70000000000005,4.85416666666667,-6.94999999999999));
#1067=CARTESIAN_POINT('',(7.70000000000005,4.92708333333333,-6.94999999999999));
#1068=CARTESIAN_POINT('',(7.70000000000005,5.07291666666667,-6.94999999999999));
#1069=CARTESIAN_POINT('',(7.70000000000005,5.14583333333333,-6.94999999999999));
#1070=CARTESIAN_POINT('',(7.70000000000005,5.29166666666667,-6.94999999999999));
#1071=CARTESIAN_POINT('',(7.70000000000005,5.36458333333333,-6.94999999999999));
#1072=CARTESIAN_POINT('',(7.70000000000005,5.51041666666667,-6.94999999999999));
#1073=CARTESIAN_POINT('',(7.70000000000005,5.58333333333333,-6.94999999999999));
#1074=CARTESIAN_POINT('',(7.70000000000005,5.72916666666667,-6.94999999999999));
#1075=CARTESIAN_POINT('',(7.70000000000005,5.80208333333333,-6.94999999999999));
#1076=CARTESIAN_POINT('',(7.70000000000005,5.94791666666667,-6.94999999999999));
#1077=CARTESIAN_POINT('',(7.70000000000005,6.02083333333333,-6.94999999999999));
#1078=CARTESIAN_POINT('',(7.70000000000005,6.16666666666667,-6.94999999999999));
#1079=CARTESIAN_POINT('',(7.70000000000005,6.23958333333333,-6.94999999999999));
#1080=CARTESIAN_POINT('',(7.70000000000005,6.38541666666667,-6.94999999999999));
#1081=CARTESIAN_POINT('',(7.70000000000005,6.45833333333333,-6.94999999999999));
#1082=CARTESIAN_POINT('',(7.70000000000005,6.60416666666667,-6.94999999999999));
#1083=CARTESIAN_POINT('',(7.70000000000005,6.67708333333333,-6.94999999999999));
#1084=CARTESIAN_POINT('',(7.70000000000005,6.82291666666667,-6.94999999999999));
#1085=CARTESIAN_POINT('',(7.70000000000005,6.89583333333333,-6.94999999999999));
#1086=CARTESIAN_POINT('',(7.70000000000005,7.04166666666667,-6.94999999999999));
#1087=CARTESIAN_POINT('',(7.70000000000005,7.11458333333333,-6.94999999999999));
#1088=CARTESIAN_POINT('',(7.70000000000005,7.26041666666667,-6.94999999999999));
#1089=CARTESIAN_POINT('',(7.70000000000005,7.33333333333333,-6.94999999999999));
#1090=CARTESIAN_POINT('',(7.70000000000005,7.47916666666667,-6.94999999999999));
#1091=CARTESIAN_POINT('',(7.70000000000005,7.55208333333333,-6.94999999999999));
#1092=CARTESIAN_POINT('',(7.70000000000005,7.69791666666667,-6.94999999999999));
#1093=CARTESIAN_POINT('',(7.70000000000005,7.77083333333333,-6.94999999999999));
#1094=CARTESIAN_POINT('',(7.70000000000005,7.91666666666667,-6.94999999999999));
#1095=CARTESIAN_POINT('',(7.70000000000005,7.98958333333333,-6.94999999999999));
#1096=CARTESIAN_POINT('',(7.70000000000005,8.13541666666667,-6.94999999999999));
#1097=CARTESIAN_POINT('',(7.70000000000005,8.20833333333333,-6.94999999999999));
#1098=CARTESIAN_POINT('',(7.70000000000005,8.35416666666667,-6.94999999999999));
#1099=CARTESIAN_POINT('',(7.70000000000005,8.42708333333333,-6.94999999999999));
#1100=CARTESIAN_POINT('',(7.70000000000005,8.5,-6.94999999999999));
#1101=B_SPLINE_CURVE_WITH_KNOTS('',3,(#1035,#1036,#1037,#1038,#1039,#1040,#1041,#1042,#1043,
#1044,#1045,#1046,#1047,#1048,#1049,#1050,#1051,#1052,#1053,#1054,#1055,#1056,#1057,#1058,#1059,
#1060,#1061,#1062,#1063,#1064,#1065,#1066,#1067,#1068,#1069,#1070,#1071,#1072,#1073,#1074,#1075,
#1076,#1077,#1078,#1079,#1080,#1081,#1082,#1083,#1084,#1085,#1086,#1087,#1088,#1089,#1090,#1091,
#1092,#1093,#1094,#1095,#1096,#1097,#1098,#1099,#1100),.UNSPECIFIED.,.F.,.F.,(4,2,2,2,2,2,2,2,2,
2,2,2,2,2,2,2,2,2,2,2,2,2,2,2,2,2,2,2,2,2,2,2,4),(0.,0.21875,0.4375,0.65625,0.875,1.09375,
1.3125,1.53125,1.75,1.96875,2.1875,2.40625,2.625,2.84375,3.0625,3.28125,3.5,3.71875,3.9375,
4.15625,4.375,4.59375,4.8125,5.03125,5.25,5.46875,5.6875,5.90625,6.125,6.34375,6.5625,6.78125,
7.),.UNSPECIFIED.);
#1102=EDGE_CURVE('BSEAM403',#1033,#242,#1101,.T.);
#1103=ORIENTED_EDGE('',*,*,#1034,.F.);
#1104=ORIENTED_EDGE('',*,*,#243,.T.);
#1105=ORIENTED_EDGE('',*,*,#1102,.T.);
#1106=ORIENTED_EDGE('',*,*,#1102,.F.);
#1107=EDGE_LOOP('',(#1103,#1105,#1104,#1106));
#1108=FACE_BOUND('',#1107,.T.);
#1109=ADVANCED_FACE('F403',(#1108),#1026,.F.);
#1110=CARTESIAN_POINT('',(7.70000000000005,1.5,-7.69999999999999));
#1111=DIRECTION('',(0.,1.,0.));
#1112=DIRECTION('',(0.,0.,1.));
#1113=AXIS2_PLACEMENT_3D('',#1110,#1111,#1112);
#1114=PLANE('',#1113);
#1115=ORIENTED_EDGE('',*,*,#1034,.T.);
#1116=EDGE_LOOP('',(#1115));
#1117=FACE_BOUND('',#1116,.T.);
#1118=ADVANCED_FACE('F412',(#1117),#1114,.T.);
#1119=CARTESIAN_POINT('',(5.20000000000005,1.5,-7.69999999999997));
#1120=DIRECTION('',(0.,1.,0.));
#1121=DIRECTION('',(0.,0.,1.));
#1122=AXIS2_PLACEMENT_3D('',#1119,#1120,#1121);
#1123=CYLINDRICAL_SURFACE('',#1122,0.75);
#1124=CARTESIAN_POINT('',(5.20000000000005,1.5,-7.69999999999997));
#1125=DIRECTION('',(0.,1.,0.));
#1126=DIRECTION('',(0.,0.,1.));
#1127=AXIS2_PLACEMENT_3D('',#1124,#1125,#1126);
#1128=CIRCLE('',#1127,0.75);
#1129=CARTESIAN_POINT('',(5.20000000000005,1.5,-6.94999999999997));
#1130=VERTEX_POINT('',#1129);
#1131=EDGE_CURVE('E154',#1130,#1130,#1128,.T.);
#1132=CARTESIAN_POINT('',(5.20000000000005,1.5,-6.94999999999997));
#1133=CARTESIAN_POINT('',(5.20000000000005,1.57291666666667,-6.94999999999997));
#1134=CARTESIAN_POINT('',(5.20000000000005,1.64583333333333,-6.94999999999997));
#1135=CARTESIAN_POINT('',(5.20000000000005,1.79166666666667,-6.94999999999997));
#1136=CARTESIAN_POINT('',(5.20000000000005,1.86458333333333,-6.94999999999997));
#1137=CARTESIAN_POINT('',(5.20000000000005,2.01041666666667,-6.94999999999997));
#1138=CARTESIAN_POINT('',(5.20000000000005,2.08333333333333,-6.94999999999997));
#1139=CARTESIAN_POINT('',(5.20000000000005,2.22916666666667,-6.94999999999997));
#1140=CARTESIAN_POINT('',(5.20000000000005,2.30208333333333,-6.94999999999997));
#1141=CARTESIAN_POINT('',(5.20000000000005,2.44791666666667,-6.94999999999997));
#1142=CARTESIAN_POINT('',(5.20000000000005,2.52083333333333,-6.94999999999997));
#1143=CARTESIAN_POINT('',(5.20000000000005,2.66666666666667,-6.94999999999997));
#1144=CARTESIAN_POINT('',(5.20000000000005,2.73958333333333,-6.94999999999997));
#1145=CARTESIAN_POINT('',(5.20000000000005,2.88541666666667,-6.94999999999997));
#1146=CARTESIAN_POINT('',(5.20000000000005,2.95833333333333,-6.94999999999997));
#1147=CARTESIAN_POINT('',(5.20000000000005,3.10416666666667,-6.94999999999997));
#1148=CARTESIAN_POINT('',(5.20000000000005,3.17708333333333,-6.94999999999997));
#1149=CARTESIAN_POINT('',(5.20000000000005,3.32291666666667,-6.94999999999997));
#1150=CARTESIAN_POINT('',(5.20000000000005,3.39583333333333,-6.94999999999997));
#1151=CARTESIAN_POINT('',(5.20000000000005,3.54166666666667,-6.94999999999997));
#1152=CARTESIAN_POINT('',(5.20000000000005,3.61458333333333,-6.94999999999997));
#1153=CARTESIAN_POINT('',(5.20000000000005,3.76041666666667,-6.94999999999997));
#1154=CARTESIAN_POINT('',(5.20000000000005,3.83333333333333,-6.94999999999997));
#1155=CARTESIAN_POINT('',(5.20000000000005,3.97916666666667,-6.94999999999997));
#1156=CARTESIAN_POINT('',(5.20000000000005,4.05208333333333,-6.94999999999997));
#1157=CARTESIAN_POINT('',(5.20000000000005,4.19791666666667,-6.94999999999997));
#1158=CARTESIAN_POINT('',(5.20000000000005,4.27083333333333,-6.94999999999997));
#1159=CARTESIAN_POINT('',(5.20000000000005,4.41666666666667,-6.94999999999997));
#1160=CARTESIAN_POINT('',(5.20000000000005,4.48958333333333,-6.94999999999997));
#1161=CARTESIAN_POINT('',(5.20000000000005,4.63541666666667,-6.94999999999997));
#1162=CARTESIAN_POINT('',(5.20000000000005,4.70833333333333,-6.94999999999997));
#1163=CARTESIAN_POINT('',(5.20000000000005,4.85416666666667,-6.94999999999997));
#1164=CARTESIAN_POINT('',(5.20000000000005,4.92708333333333,-6.94999999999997));
#1165=CARTESIAN_POINT('',(5.20000000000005,5.07291666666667,-6.94999999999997));
#1166=CARTESIAN_POINT('',(5.20000000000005,5.14583333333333,-6.94999999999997));
#1167=CARTESIAN_POINT('',(5.20000000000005,5.29166666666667,-6.94999999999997));
#1168=CARTESIAN_POINT('',(5.20000000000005,5.36458333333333,-6.94999999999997));
#1169=CARTESIAN_POINT('',(5.20000000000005,5.51041666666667,-6.94999999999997));
#1170=CARTESIAN_POINT('',(5.20000000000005,5.58333333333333,-6.94999999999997));
#1171=CARTESIAN_POINT('',(5.20000000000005,5.72916666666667,-6.94999999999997));
#1172=CARTESIAN_POINT('',(5.20000000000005,5.80208333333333,-6.94999999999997));
#1173=CARTESIAN_POINT('',(5.20000000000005,5.94791666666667,-6.94999999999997));
#1174=CARTESIAN_POINT('',(5.20000000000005,6.02083333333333,-6.94999999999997));
#1175=CARTESIAN_POINT('',(5.20000000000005,6.16666666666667,-6.94999999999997));
#1176=CARTESIAN_POINT('',(5.20000000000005,6.23958333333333,-6.94999999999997));
#1177=CARTESIAN_POINT('',(5.20000000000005,6.38541666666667,-6.94999999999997));
#1178=CARTESIAN_POINT('',(5.20000000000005,6.45833333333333,-6.94999999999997));
#1179=CARTESIAN_POINT('',(5.20000000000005,6.60416666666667,-6.94999999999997));
#1180=CARTESIAN_POINT('',(5.20000000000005,6.67708333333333,-6.94999999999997));
#1181=CARTESIAN_POINT('',(5.20000000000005,6.82291666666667,-6.94999999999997));
#1182=CARTESIAN_POINT('',(5.20000000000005,6.89583333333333,-6.94999999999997));
#1183=CARTESIAN_POINT('',(5.20000000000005,7.04166666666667,-6.94999999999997));
#1184=CARTESIAN_POINT('',(5.20000000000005,7.11458333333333,-6.94999999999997));
#1185=CARTESIAN_POINT('',(5.20000000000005,7.26041666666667,-6.94999999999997));
#1186=CARTESIAN_POINT('',(5.20000000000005,7.33333333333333,-6.94999999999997));
#1187=CARTESIAN_POINT('',(5.20000000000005,7.47916666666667,-6.94999999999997));
#1188=CARTESIAN_POINT('',(5.20000000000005,7.55208333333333,-6.94999999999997));
#1189=CARTESIAN_POINT('',(5.20000000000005,7.69791666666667,-6.94999999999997));
#1190=CARTESIAN_POINT('',(5.20000000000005,7.77083333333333,-6.94999999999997));
#1191=CARTESIAN_POINT('',(5.20000000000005,7.91666666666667,-6.94999999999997));
#1192=CARTESIAN_POINT('',(5.20000000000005,7.98958333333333,-6.94999999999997));
#1193=CARTESIAN_POINT('',(5.20000000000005,8.13541666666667,-6.94999999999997));
#1194=CARTESIAN_POINT('',(5.20000000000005,8.20833333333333,-6.94999999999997));
#1195=CARTESIAN_POINT('',(5.20000000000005,8.35416666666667,-6.94999999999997));
#1196=CARTESIAN_POINT('',(5.20000000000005,8.42708333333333,-6.94999999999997));
#1197=CARTESIAN_POINT('',(5.20000000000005,8.5,-6.94999999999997));
#1198=B_SPLINE_CURVE_WITH_KNOTS('',3,(#1132,#1133,#1134,#1135,#1136,#1137,#1138,#1139,#1140,
#1141,#1142,#1143,#1144,#1145,#1146,#1147,#1148,#1149,#1150,#1151,#1152,#1153,#1154,#1155,#1156,
#1157,#1158,#1159,#1160,#1161,#1162,#1163,#1164,#1165,#1166,#1167,#1168,#1169,#1170,#1171,#1172,
#1173,#1174,#1175,#1176,#1177,#1178,#1179,#1180,#1181,#1182,#1183,#1184,#1185,#1186,#1187,#1188,
#1189,#1190,#1191,#1192,#1193,#1194,#1195,#1196,#1197),.UNSPECIFIED.,.F.,.F.,(4,2,2,2,2,2,2,2,2,
2,2,2,2,2,2,2,2,2,2,2,2,2,2,2,2,2,2,2,2,2,2,2,4),(0.,0.21875,0.4375,0.65625,0.875,1.09375,
1.3125,1.53125,1.75,1.96875,2.1875,2.40625,2.625,2.84375,3.0625,3.28125,3.5,3.71875,3.9375,
4.15625,4.375,4.59375,4.8125,5.03125,5.25,5.46875,5.6875,5.90625,6.125,6.34375,6.5625,6.78125,
7.),.UNSPECIFIED.);
#1199=EDGE_CURVE('BSEAM421',#1130,#231,#1198,.T.);
#1200=ORIENTED_EDGE('',*,*,#1131,.F.);
#1201=ORIENTED_EDGE('',*,*,#232,.T.);
#1202=ORIENTED_EDGE('',*,*,#1199,.T.);
#1203=ORIENTED_EDGE('',*,*,#1199,.F.);
#1204=EDGE_LOOP('',(#1200,#1202,#1201,#1203));
#1205=FACE_BOUND('',#1204,.T.);
#1206=ADVANCED_FACE('F421',(#1205),#1123,.F.);
#1207=CARTESIAN_POINT('',(5.20000000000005,1.5,-7.69999999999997));
#1208=DIRECTION('',(0.,1.,0.));
#1209=DIRECTION('',(0.,0.,1.));
#1210=AXIS2_PLACEMENT_3D('',#1207,#1208,#1209);
#1211=PLANE('',#1210);
#1212=ORIENTED_EDGE('',*,*,#1131,.T.);
#1213=EDGE_LOOP('',(#1212));
#1214=FACE_BOUND('',#1213,.T.);
#1215=ADVANCED_FACE('F430',(#1214),#1211,.T.);
#1216=CARTESIAN_POINT('',(2.70000000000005,1.5,-7.69999999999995));
#1217=DIRECTION('',(0.,1.,0.));
#1218=DIRECTION('',(0.,0.,1.));
#1219=AXIS2_PLACEMENT_3D('',#1216,#1217,#1218);
#1220=CYLINDRICAL_SURFACE('',#1219,0.75);
#1221=CARTESIAN_POINT('',(2.70000000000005,1.5,-7.69999999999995));
#1222=DIRECTION('',(0.,1.,0.));
#1223=DIRECTION('',(0.,0.,1.));
#1224=AXIS2_PLACEMENT_3D('',#1221,#1222,#1223);
#1225=CIRCLE('',#1224,0.75);
#1226=CARTESIAN_POINT('',(2.70000000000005,1.5,-6.94999999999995));
#1227=VERTEX_POINT('',#1226);
#1228=EDGE_CURVE('E160',#1227,#1227,#1225,.T.);
#1229=CARTESIAN_POINT('',(2.70000000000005,1.5,-6.94999999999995));
#1230=CARTESIAN_POINT('',(2.70000000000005,1.57291666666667,-6.94999999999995));
#1231=CARTESIAN_POINT('',(2.70000000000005,1.64583333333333,-6.94999999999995));
#1232=CARTESIAN_POINT('',(2.70000000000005,1.79166666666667,-6.94999999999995));
#1233=CARTESIAN_POINT('',(2.70000000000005,1.86458333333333,-6.94999999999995));
#1234=CARTESIAN_POINT('',(2.70000000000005,2.01041666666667,-6.94999999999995));
#1235=CARTESIAN_POINT('',(2.70000000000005,2.08333333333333,-6.94999999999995));
#1236=CARTESIAN_POINT('',(2.70000000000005,2.22916666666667,-6.94999999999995));
#1237=CARTESIAN_POINT('',(2.70000000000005,2.30208333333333,-6.94999999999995));
#1238=CARTESIAN_POINT('',(2.70000000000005,2.44791666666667,-6.94999999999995));
#1239=CARTESIAN_POINT('',(2.70000000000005,2.52083333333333,-6.94999999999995));
#1240=CARTESIAN_POINT('',(2.70000000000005,2.66666666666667,-6.94999999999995));
#1241=CARTESIAN_POINT('',(2.70000000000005,2.73958333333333,-6.94999999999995));
#1242=CARTESIAN_POINT('',(2.70000000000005,2.88541666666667,-6.94999999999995));
#1243=CARTESIAN_POINT('',(2.70000000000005,2.95833333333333,-6.94999999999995));
#1244=CARTESIAN_POINT('',(2.70000000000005,3.10416666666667,-6.94999999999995));
#1245=CARTESIAN_POINT('',(2.70000000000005,3.17708333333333,-6.94999999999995));
#1246=CARTESIAN_POINT('',(2.70000000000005,3.32291666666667,-6.94999999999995));
#1247=CARTESIAN_POINT('',(2.70000000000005,3.39583333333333,-6.94999999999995));
#1248=CARTESIAN_POINT('',(2.70000000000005,3.54166666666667,-6.94999999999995));
#1249=CARTESIAN_POINT('',(2.70000000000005,3.61458333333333,-6.94999999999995));
#1250=CARTESIAN_POINT('',(2.70000000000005,3.76041666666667,-6.94999999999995));
#1251=CARTESIAN_POINT('',(2.70000000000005,3.83333333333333,-6.94999999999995));
#1252=CARTESIAN_POINT('',(2.70000000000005,3.97916666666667,-6.94999999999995));
#1253=CARTESIAN_POINT('',(2.70000000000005,4.05208333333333,-6.94999999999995));
#1254=CARTESIAN_POINT('',(2.70000000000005,4.19791666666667,-6.94999999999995));
#1255=CARTESIAN_POINT('',(2.70000000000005,4.27083333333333,-6.94999999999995));
#1256=CARTESIAN_POINT('',(2.70000000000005,4.41666666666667,-6.94999999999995));
#1257=CARTESIAN_POINT('',(2.70000000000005,4.48958333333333,-6.94999999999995));
#1258=CARTESIAN_POINT('',(2.70000000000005,4.63541666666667,-6.94999999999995));
#1259=CARTESIAN_POINT('',(2.70000000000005,4.70833333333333,-6.94999999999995));
#1260=CARTESIAN_POINT('',(2.70000000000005,4.85416666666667,-6.94999999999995));
#1261=CARTESIAN_POINT('',(2.70000000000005,4.92708333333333,-6.94999999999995));
#1262=CARTESIAN_POINT('',(2.70000000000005,5.07291666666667,-6.94999999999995));
#1263=CARTESIAN_POINT('',(2.70000000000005,5.14583333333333,-6.94999999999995));
#1264=CARTESIAN_POINT('',(2.70000000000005,5.29166666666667,-6.94999999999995));
#1265=CARTESIAN_POINT('',(2.70000000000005,5.36458333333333,-6.94999999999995));
#1266=CARTESIAN_POINT('',(2.70000000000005,5.51041666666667,-6.94999999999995));
#1267=CARTESIAN_POINT('',(2.70000000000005,5.58333333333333,-6.94999999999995));
#1268=CARTESIAN_POINT('',(2.70000000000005,5.72916666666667,-6.94999999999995));
#1269=CARTESIAN_POINT('',(2.70000000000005,5.80208333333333,-6.94999999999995));
#1270=CARTESIAN_POINT('',(2.70000000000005,5.94791666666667,-6.94999999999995));
#1271=CARTESIAN_POINT('',(2.70000000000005,6.02083333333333,-6.94999999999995));
#1272=CARTESIAN_POINT('',(2.70000000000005,6.16666666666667,-6.94999999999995));
#1273=CARTESIAN_POINT('',(2.70000000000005,6.23958333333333,-6.94999999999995));
#1274=CARTESIAN_POINT('',(2.70000000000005,6.38541666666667,-6.94999999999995));
#1275=CARTESIAN_POINT('',(2.70000000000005,6.45833333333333,-6.94999999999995));
#1276=CARTESIAN_POINT('',(2.70000000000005,6.60416666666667,-6.94999999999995));
#1277=CARTESIAN_POINT('',(2.70000000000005,6.67708333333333,-6.94999999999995));
#1278=CARTESIAN_POINT('',(2.70000000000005,6.82291666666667,-6.94999999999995));
#1279=CARTESIAN_POINT('',(2.70000000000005,6.89583333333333,-6.94999999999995));
#1280=CARTESIAN_POINT('',(2.70000000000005,7.04166666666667,-6.94999999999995));
#1281=CARTESIAN_POINT('',(2.70000000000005,7.11458333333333,-6.94999999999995));
#1282=CARTESIAN_POINT('',(2.70000000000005,7.26041666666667,-6.94999999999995));
#1283=CARTESIAN_POINT('',(2.70000000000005,7.33333333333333,-6.94999999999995));
#1284=CARTESIAN_POINT('',(2.70000000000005,7.47916666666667,-6.94999999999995));
#1285=CARTESIAN_POINT('',(2.70000000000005,7.55208333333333,-6.94999999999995));
#1286=CARTESIAN_POINT('',(2.70000000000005,7.69791666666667,-6.94999999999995));
#1287=CARTESIAN_POINT('',(2.70000000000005,7.77083333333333,-6.94999999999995));
#1288=CARTESIAN_POINT('',(2.70000000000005,7.91666666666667,-6.94999999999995));
#1289=CARTESIAN_POINT('',(2.70000000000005,7.98958333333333,-6.94999999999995));
#1290=CARTESIAN_POINT('',(2.70000000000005,8.13541666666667,-6.94999999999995));
#1291=CARTESIAN_POINT('',(2.70000000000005,8.20833333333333,-6.94999999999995));
#1292=CARTESIAN_POINT('',(2.70000000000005,8.35416666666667,-6.94999999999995));
#1293=CARTESIAN_POINT('',(2.70000000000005,8.42708333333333,-6.94999999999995));
#1294=CARTESIAN_POINT('',(2.70000000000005,8.5,-6.94999999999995));
#1295=B_SPLINE_CURVE_WITH_KNOTS('',3,(#1229,#1230,#1231,#1232,#1233,#1234,#1235,#1236,#1237,
#1238,#1239,#1240,#1241,#1242,#1243,#1244,#1245,#1246,#1247,#1248,#1249,#1250,#1251,#1252,#1253,
#1254,#1255,#1256,#1257,#1258,#1259,#1260,#1261,#1262,#1263,#1264,#1265,#1266,#1267,#1268,#1269,
#1270,#1271,#1272,#1273,#1274,#1275,#1276,#1277,#1278,#1279,#1280,#1281,#1282,#1283,#1284,#1285,
#1286,#1287,#1288,#1289,#1290,#1291,#1292,#1293,#1294),.UNSPECIFIED.,.F.,.F.,(4,2,2,2,2,2,2,2,2,
2,2,2,2,2,2,2,2,2,2,2,2,2,2,2,2,2,2,2,2,2,2,2,4),(0.,0.21875,0.4375,0.65625,0.875,1.09375,
1.3125,1.53125,1.75,1.96875,2.1875,2.40625,2.625,2.84375,3.0625,3.28125,3.5,3.71875,3.9375,
4.15625,4.375,4.59375,4.8125,5.03125,5.25,5.46875,5.6875,5.90625,6.125,6.34375,6.5625,6.78125,
7.),.UNSPECIFIED.);
#1296=EDGE_CURVE('BSEAM439',#1227,#220,#1295,.T.);
#1297=ORIENTED_EDGE('',*,*,#1228,.F.);
#1298=ORIENTED_EDGE('',*,*,#221,.T.);
#1299=ORIENTED_EDGE('',*,*,#1296,.T.);
#1300=ORIENTED_EDGE('',*,*,#1296,.F.);
#1301=EDGE_LOOP('',(#1297,#1299,#1298,#1300));
#1302=FACE_BOUND('',#1301,.T.);
#1303=ADVANCED_FACE('F439',(#1302),#1220,.F.);
#1304=CARTESIAN_POINT('',(2.70000000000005,1.5,-7.69999999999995));
#1305=DIRECTION('',(0.,1.,0.));
#1306=DIRECTION('',(0.,0.,1.));
#1307=AXIS2_PLACEMENT_3D('',#1304,#1305,#1306);
#1308=PLANE('',#1307);
#1309=ORIENTED_EDGE('',*,*,#1228,.T.);
#1310=EDGE_LOOP('',(#1309));
#1311=FACE_BOUND('',#1310,.T.);
#1312=ADVANCED_FACE('F448',(#1311),#1308,.T.);
#1313=CARTESIAN_POINT('',(7.70000000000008,1.5,-5.19999999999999));
#1314=DIRECTION('',(0.,1.,0.));
#1315=DIRECTION('',(0.,0.,1.));
#1316=AXIS2_PLACEMENT_3D('',#1313,#1314,#1315);
#1317=CYLINDRICAL_SURFACE('',#1316,0.750000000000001);
#1318=CARTESIAN_POINT('',(7.70000000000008,1.5,-5.19999999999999));
#1319=DIRECTION('',(0.,1.,0.));
#1320=DIRECTION('',(0.,0.,1.));
#1321=AXIS2_PLACEMENT_3D('',#1318,#1319,#1320);
#1322=CIRCLE('',#1321,0.750000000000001);
#1323=CARTESIAN_POINT('',(7.70000000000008,1.5,-4.44999999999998));
#1324=VERTEX_POINT('',#1323);
#1325=EDGE_CURVE('E166',#1324,#1324,#1322,.T.);
#1326=CARTESIAN_POINT('',(7.70000000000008,1.5,-4.44999999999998));
#1327=CARTESIAN_POINT('',(7.70000000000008,1.57291666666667,-4.44999999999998));
#1328=CARTESIAN_POINT('',(7.70000000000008,1.64583333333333,-4.44999999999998));
#1329=CARTESIAN_POINT('',(7.70000000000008,1.79166666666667,-4.44999999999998));
#1330=CARTESIAN_POINT('',(7.70000000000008,1.86458333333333,-4.44999999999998));
#1331=CARTESIAN_POINT('',(7.70000000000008,2.01041666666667,-4.44999999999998));
#1332=CARTESIAN_POINT('',(7.70000000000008,2.08333333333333,-4.44999999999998));
#1333=CARTESIAN_POINT('',(7.70000000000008,2.22916666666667,-4.44999999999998));
#1334=CARTESIAN_POINT('',(7.70000000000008,2.30208333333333,-4.44999999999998));
#1335=CARTESIAN_POINT('',(7.70000000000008,2.44791666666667,-4.44999999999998));
#1336=CARTESIAN_POINT('',(7.70000000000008,2.52083333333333,-4.44999999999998));
#1337=CARTESIAN_POINT('',(7.70000000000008,2.66666666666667,-4.44999999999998));
#1338=CARTESIAN_POINT('',(7.70000000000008,2.73958333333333,-4.44999999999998));
#1339=CARTESIAN_POINT('',(7.70000000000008,2.88541666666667,-4.44999999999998));
#1340=CARTESIAN_POINT('',(7.70000000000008,2.95833333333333,-4.44999999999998));
#1341=CARTESIAN_POINT('',(7.70000000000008,3.10416666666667,-4.44999999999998));
#1342=CARTESIAN_POINT('',(7.70000000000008,3.17708333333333,-4.44999999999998));
#1343=CARTESIAN_POINT('',(7.70000000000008,3.32291666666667,-4.44999999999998));
#1344=CARTESIAN_POINT('',(7.70000000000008,3.39583333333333,-4.44999999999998));
#1345=CARTESIAN_POINT('',(7.70000000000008,3.54166666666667,-4.44999999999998));
#1346=CARTESIAN_POINT('',(7.70000000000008,3.61458333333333,-4.44999999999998));
#1347=CARTESIAN_POINT('',(7.70000000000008,3.76041666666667,-4.44999999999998));
#1348=CARTESIAN_POINT('',(7.70000000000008,3.83333333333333,-4.44999999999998));
#1349=CARTESIAN_POINT('',(7.70000000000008,3.97916666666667,-4.44999999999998));
#1350=CARTESIAN_POINT('',(7.70000000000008,4.05208333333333,-4.44999999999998));
#1351=CARTESIAN_POINT('',(7.70000000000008,4.19791666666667,-4.44999999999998));
#1352=CARTESIAN_POINT('',(7.70000000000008,4.27083333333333,-4.44999999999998));
#1353=CARTESIAN_POINT('',(7.70000000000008,4.41666666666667,-4.44999999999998));
#1354=CARTESIAN_POINT('',(7.70000000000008,4.48958333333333,-4.44999999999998));
#1355=CARTESIAN_POINT('',(7.70000000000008,4.63541666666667,-4.44999999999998));
#1356=CARTESIAN_POINT('',(7.70000000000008,4.70833333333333,-4.44999999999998));
#1357=CARTESIAN_POINT('',(7.70000000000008,4.85416666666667,-4.44999999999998));
#1358=CARTESIAN_POINT('',(7.70000000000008,4.92708333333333,-4.44999999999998));
#1359=CARTESIAN_POINT('',(7.70000000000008,5.07291666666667,-4.44999999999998));
#1360=CARTESIAN_POINT('',(7.70000000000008,5.14583333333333,-4.44999999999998));
#1361=CARTESIAN_POINT('',(7.70000000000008,5.29166666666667,-4.44999999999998));
#1362=CARTESIAN_POINT('',(7.70000000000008,5.36458333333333,-4.44999999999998));
#1363=CARTESIAN_POINT('',(7.70000000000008,5.51041666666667,-4.44999999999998));
#1364=CARTESIAN_POINT('',(7.70000000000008,5.58333333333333,-4.44999999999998));
#1365=CARTESIAN_POINT('',(7.70000000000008,5.72916666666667,-4.44999999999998));
#1366=CARTESIAN_POINT('',(7.70000000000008,5.80208333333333,-4.44999999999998));
#1367=CARTESIAN_POINT('',(7.70000000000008,5.94791666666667,-4.44999999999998));
#1368=CARTESIAN_POINT('',(7.70000000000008,6.02083333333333,-4.44999999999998));
#1369=CARTESIAN_POINT('',(7.70000000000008,6.16666666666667,-4.44999999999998));
#1370=CARTESIAN_POINT('',(7.70000000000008,6.23958333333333,-4.44999999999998));
#1371=CARTESIAN_POINT('',(7.70000000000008,6.38541666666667,-4.44999999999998));
#1372=CARTESIAN_POINT('',(7.70000000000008,6.45833333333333,-4.44999999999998));
#1373=CARTESIAN_POINT('',(7.70000000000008,6.60416666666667,-4.44999999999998));
#1374=CARTESIAN_POINT('',(7.70000000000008,6.67708333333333,-4.44999999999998));
#1375=CARTESIAN_POINT('',(7.70000000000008,6.82291666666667,-4.44999999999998));
#1376=CARTESIAN_POINT('',(7.70000000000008,6.89583333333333,-4.44999999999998));
#1377=CARTESIAN_POINT('',(7.70000000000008,7.04166666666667,-4.44999999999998));
#1378=CARTESIAN_POINT('',(7.70000000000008,7.11458333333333,-4.44999999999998));
#1379=CARTESIAN_POINT('',(7.70000000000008,7.26041666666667,-4.44999999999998));
#1380=CARTESIAN_POINT('',(7.70000000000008,7.33333333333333,-4.44999999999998));
#1381=CARTESIAN_POINT('',(7.70000000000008,7.47916666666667,-4.44999999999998));
#1382=CARTESIAN_POINT('',(7.70000000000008,7.55208333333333,-4.44999999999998));
#1383=CARTESIAN_POINT('',(7.70000000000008,7.69791666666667,-4.44999999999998));
#1384=CARTESIAN_POINT('',(7.70000000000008,7.77083333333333,-4.44999999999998));
#1385=CARTESIAN_POINT('',(7.70000000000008,7.91666666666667,-4.44999999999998));
#1386=CARTESIAN_POINT('',(7.70000000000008,7.98958333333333,-4.44999999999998));
#1387=CARTESIAN_POINT('',(7.70000000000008,8.13541666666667,-4.44999999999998));
#1388=CARTESIAN_POINT('',(7.70000000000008,8.20833333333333,-4.44999999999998));
#1389=CARTESIAN_POINT('',(7.70000000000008,8.35416666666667,-4.44999999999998));
#1390=CARTESIAN_POINT('',(7.70000000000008,8.42708333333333,-4.44999999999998));
#1391=CARTESIAN_POINT('',(7.70000000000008,8.5,-4.44999999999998));
#1392=B_SPLINE_CURVE_WITH_KNOTS('',3,(#1326,#1327,#1328,#1329,#1330,#1331,#1332,#1333,#1334,
#1335,#1336,#1337,#1338,#1339,#1340,#1341,#1342,#1343,#1344,#1345,#1346,#1347,#1348,#1349,#1350,
#1351,#1352,#1353,#1354,#1355,#1356,#1357,#1358,#1359,#1360,#1361,#1362,#1363,#1364,#1365,#1366,
#1367,#1368,#1369,#1370,#1371,#1372,#1373,#1374,#1375,#1376,#1377,#1378,#1379,#1380,#1381,#1382,
#1383,#1384,#1385,#1386,#1387,#1388,#1389,#1390,#1391),.UNSPECIFIED.,.F.,.F.,(4,2,2,2,2,2,2,2,2,
2,2,2,2,2,2,2,2,2,2,2,2,2,2,2,2,2,2,2,2,2,2,2,4),(0.,0.21875,0.4375,0.65625,0.875,1.09375,
1.3125,1.53125,1.75,1.96875,2.1875,2.40625,2.625,2.84375,3.0625,3.28125,3.5,3.71875,3.9375,
4.15625,4.375,4.59375,4.8125,5.03125,5.25,5.46875,5.6875,5.90625,6.125,6.34375,6.5625,6.78125,
7.),.UNSPECIFIED.);
#1393=EDGE_CURVE('BSEAM457',#1324,#209,#1392,.T.);
#1394=ORIENTED_EDGE('',*,*,#1325,.F.);
#1395=ORIENTED_EDGE('',*,*,#210,.T.);
#1396=ORIENTED_EDGE('',*,*,#1393,.T.);
#1397=ORIENTED_EDGE('',*,*,#1393,.F.);
#1398=EDGE_LOOP('',(#1394,#1396,#1395,#1397));
#1399=FACE_BOUND('',#1398,.T.);
#1400=ADVANCED_FACE('F457',(#1399),#1317,.F.);
#1401=CARTESIAN_POINT('',(7.70000000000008,1.5,-5.19999999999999));
#1402=DIRECTION('',(0.,1.,0.));
#1403=DIRECTION('',(0.,0.,1.));
#1404=AXIS2_PLACEMENT_3D('',#1401,#1402,#1403);
#1405=PLANE('',#1404);
#1406=ORIENTED_EDGE('',*,*,#1325,.T.);
#1407=EDGE_LOOP('',(#1406));
#1408=FACE_BOUND('',#1407,.T.);
#1409=ADVANCED_FACE('F466',(#1408),#1405,.T.);
#1410=CARTESIAN_POINT('',(5.20000000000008,1.5,-5.19999999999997));
#1411=DIRECTION('',(0.,1.,0.));
#1412=DIRECTION('',(0.,0.,1.));
#1413=AXIS2_PLACEMENT_3D('',#1410,#1411,#1412);
#1414=CYLINDRICAL_SURFACE('',#1413,0.75);
#1415=CARTESIAN_POINT('',(5.20000000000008,1.5,-5.19999999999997));
#1416=DIRECTION('',(0.,1.,0.));
#1417=DIRECTION('',(0.,0.,1.));
#1418=AXIS2_PLACEMENT_3D('',#1415,#1416,#1417);
#1419=CIRCLE('',#1418,0.75);
#1420=CARTESIAN_POINT('',(5.20000000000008,1.5,-4.44999999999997));
#1421=VERTEX_POINT('',#1420);
#1422=EDGE_CURVE('E172',#1421,#1421,#1419,.T.);
#1423=CARTESIAN_POINT('',(5.20000000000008,1.5,-4.44999999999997));
#1424=CARTESIAN_POINT('',(5.20000000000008,1.57291666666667,-4.44999999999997));
#1425=CARTESIAN_POINT('',(5.20000000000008,1.64583333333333,-4.44999999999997));
#1426=CARTESIAN_POINT('',(5.20000000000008,1.79166666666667,-4.44999999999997));
#1427=CARTESIAN_POINT('',(5.20000000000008,1.86458333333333,-4.44999999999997));
#1428=CARTESIAN_POINT('',(5.20000000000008,2.01041666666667,-4.44999999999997));
#1429=CARTESIAN_POINT('',(5.20000000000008,2.08333333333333,-4.44999999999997));
#1430=CARTESIAN_POINT('',(5.20000000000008,2.22916666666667,-4.44999999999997));
#1431=CARTESIAN_POINT('',(5.20000000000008,2.30208333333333,-4.44999999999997));
#1432=CARTESIAN_POINT('',(5.20000000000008,2.44791666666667,-4.44999999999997));
#1433=CARTESIAN_POINT('',(5.20000000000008,2.52083333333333,-4.44999999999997));
#1434=CARTESIAN_POINT('',(5.20000000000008,2.66666666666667,-4.44999999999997));
#1435=CARTESIAN_POINT('',(5.20000000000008,2.73958333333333,-4.44999999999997));
#1436=CARTESIAN_POINT('',(5.20000000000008,2.88541666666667,-4.44999999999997));
#1437=CARTESIAN_POINT('',(5.20000000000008,2.95833333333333,-4.44999999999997));
#1438=CARTESIAN_POINT('',(5.20000000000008,3.10416666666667,-4.44999999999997));
#1439=CARTESIAN_POINT('',(5.20000000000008,3.17708333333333,-4.44999999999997));
#1440=CARTESIAN_POINT('',(5.20000000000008,3.32291666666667,-4.44999999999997));
#1441=CARTESIAN_POINT('',(5.20000000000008,3.39583333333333,-4.44999999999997));
#1442=CARTESIAN_POINT('',(5.20000000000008,3.54166666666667,-4.44999999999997));
#1443=CARTESIAN_POINT('',(5.20000000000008,3.61458333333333,-4.44999999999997));
#1444=CARTESIAN_POINT('',(5.20000000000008,3.76041666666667,-4.44999999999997));
#1445=CARTESIAN_POINT('',(5.20000000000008,3.83333333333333,-4.44999999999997));
#1446=CARTESIAN_POINT('',(5.20000000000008,3.97916666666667,-4.44999999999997));
#1447=CARTESIAN_POINT('',(5.20000000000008,4.05208333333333,-4.44999999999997));
#1448=CARTESIAN_POINT('',(5.20000000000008,4.19791666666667,-4.44999999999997));
#1449=CARTESIAN_POINT('',(5.20000000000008,4.27083333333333,-4.44999999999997));
#1450=CARTESIAN_POINT('',(5.20000000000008,4.41666666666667,-4.44999999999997));
#1451=CARTESIAN_POINT('',(5.20000000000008,4.48958333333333,-4.44999999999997));
#1452=CARTESIAN_POINT('',(5.20000000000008,4.63541666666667,-4.44999999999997));
#1453=CARTESIAN_POINT('',(5.20000000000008,4.70833333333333,-4.44999999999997));
#1454=CARTESIAN_POINT('',(5.20000000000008,4.85416666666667,-4.44999999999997));
#1455=CARTESIAN_POINT('',(5.20000000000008,4.92708333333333,-4.44999999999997));
#1456=CARTESIAN_POINT('',(5.20000000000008,5.07291666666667,-4.44999999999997));
#1457=CARTESIAN_POINT('',(5.20000000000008,5.14583333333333,-4.44999999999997));
#1458=CARTESIAN_POINT('',(5.20000000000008,5.29166666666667,-4.44999999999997));
#1459=CARTESIAN_POINT('',(5.20000000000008,5.36458333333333,-4.44999999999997));
#1460=CARTESIAN_POINT('',(5.20000000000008,5.51041666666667,-4.44999999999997));
#1461=CARTESIAN_POINT('',(5.20000000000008,5.58333333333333,-4.44999999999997));
#1462=CARTESIAN_POINT('',(5.20000000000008,5.72916666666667,-4.44999999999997));
#1463=CARTESIAN_POINT('',(5.20000000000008,5.80208333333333,-4.44999999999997));
#1464=CARTESIAN_POINT('',(5.20000000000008,5.94791666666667,-4.44999999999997));
#1465=CARTESIAN_POINT('',(5.20000000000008,6.02083333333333,-4.44999999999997));
#1466=CARTESIAN_POINT('',(5.20000000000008,6.16666666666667,-4.44999999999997));
#1467=CARTESIAN_POINT('',(5.20000000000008,6.23958333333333,-4.44999999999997));
#1468=CARTESIAN_POINT('',(5.20000000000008,6.38541666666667,-4.44999999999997));
#1469=CARTESIAN_POINT('',(5.20000000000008,6.45833333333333,-4.44999999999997));
#1470=CARTESIAN_POINT('',(5.20000000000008,6.60416666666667,-4.44999999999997));
#1471=CARTESIAN_POINT('',(5.20000000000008,6.67708333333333,-4.44999999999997));
#1472=CARTESIAN_POINT('',(5.20000000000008,6.82291666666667,-4.44999999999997));
#1473=CARTESIAN_POINT('',(5.20000000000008,6.89583333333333,-4.44999999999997));
#1474=CARTESIAN_POINT('',(5.20000000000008,7.04166666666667,-4.44999999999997));
#1475=CARTESIAN_POINT('',(5.20000000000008,7.11458333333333,-4.44999999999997));
#1476=CARTESIAN_POINT('',(5.20000000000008,7.26041666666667,-4.44999999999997));
#1477=CARTESIAN_POINT('',(5.20000000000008,7.33333333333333,-4.44999999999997));
#1478=CARTESIAN_POINT('',(5.20000000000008,7.47916666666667,-4.44999999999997));
#1479=CARTESIAN_POINT('',(5.20000000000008,7.55208333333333,-4.44999999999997));
#1480=CARTESIAN_POINT('',(5.20000000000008,7.69791666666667,-4.44999999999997));
#1481=CARTESIAN_POINT('',(5.20000000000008,7.77083333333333,-4.44999999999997));
#1482=CARTESIAN_POINT('',(5.20000000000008,7.91666666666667,-4.44999999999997));
#1483=CARTESIAN_POINT('',(5.20000000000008,7.98958333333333,-4.44999999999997));
#1484=CARTESIAN_POINT('',(5.20000000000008,8.13541666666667,-4.44999999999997));
#1485=CARTESIAN_POINT('',(5.20000000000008,8.20833333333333,-4.44999999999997));
#1486=CARTESIAN_POINT('',(5.20000000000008,8.35416666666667,-4.44999999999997));
#1487=CARTESIAN_POINT('',(5.20000000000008,8.42708333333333,-4.44999999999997));
#1488=CARTESIAN_POINT('',(5.20000000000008,8.5,-4.44999999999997));
#1489=B_SPLINE_CURVE_WITH_KNOTS('',3,(#1423,#1424,#1425,#1426,#1427,#1428,#1429,#1430,#1431,
#1432,#1433,#1434,#1435,#1436,#1437,#1438,#1439,#1440,#1441,#1442,#1443,#1444,#1445,#1446,#1447,
#1448,#1449,#1450,#1451,#1452,#1453,#1454,#1455,#1456,#1457,#1458,#1459,#1460,#1461,#1462,#1463,
#1464,#1465,#1466,#1467,#1468,#1469,#1470,#1471,#1472,#1473,#1474,#1475,#1476,#1477,#1478,#1479,
#1480,#1481,#1482,#1483,#1484,#1485,#1486,#1487,#1488),.UNSPECIFIED.,.F.,.F.,(4,2,2,2,2,2,2,2,2,
2,2,2,2,2,2,2,2,2,2,2,2,2,2,2,2,2,2,2,2,2,2,2,4),(0.,0.21875,0.4375,0.65625,0.875,1.09375,
1.3125,1.53125,1.75,1.96875,2.1875,2.40625,2.625,2.84375,3.0625,3.28125,3.5,3.71875,3.9375,
4.15625,4.375,4.59375,4.8125,5.03125,5.25,5.46875,5.6875,5.90625,6.125,6.34375,6.5625,6.78125,
7.),.UNSPECIFIED.);
#1490=EDGE_CURVE('BSEAM475',#1421,#198,#1489,.T.);
#1491=ORIENTED_EDGE('',*,*,#1422,.F.);
#1492=ORIENTED_EDGE('',*,*,#199,.T.);
#1493=ORIENTED_EDGE('',*,*,#1490,.T.);
#1494=ORIENTED_EDGE('',*,*,#1490,.F.);
#1495=EDGE_LOOP('',(#1491,#1493,#1492,#1494));
#1496=FACE_BOUND('',#1495,.T.);
#1497=ADVANCED_FACE('F475',(#1496),#1414,.F.);
#1498=CARTESIAN_POINT('',(5.20000000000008,1.5,-5.19999999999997));
#1499=DIRECTION('',(0.,1.,0.));
#1500=DIRECTION('',(0.,0.,1.));
#1501=AXIS2_PLACEMENT_3D('',#1498,#1499,#1500);
#1502=PLANE('',#1501);
#1503=ORIENTED_EDGE('',*,*,#1422,.T.);
#1504=EDGE_LOOP('',(#1503));
#1505=FACE_BOUND('',#1504,.T.);
#1506=ADVANCED_FACE('F484',(#1505),#1502,.T.);
#1507=CARTESIAN_POINT('',(2.70000000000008,1.5,-5.19999999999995));
#1508=DIRECTION('',(0.,1.,0.));
#1509=DIRECTION('',(0.,0.,1.));
#1510=AXIS2_PLACEMENT_3D('',#1507,#1508,#1509);
#1511=CYLINDRICAL_SURFACE('',#1510,0.75);
#1512=CARTESIAN_POINT('',(2.70000000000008,1.5,-5.19999999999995));
#1513=DIRECTION('',(0.,1.,0.));
#1514=DIRECTION('',(0.,0.,1.));
#1515=AXIS2_PLACEMENT_3D('',#1512,#1513,#1514);
#1516=CIRCLE('',#1515,0.75);
#1517=CARTESIAN_POINT('',(2.70000000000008,1.5,-4.44999999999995));
#1518=VERTEX_POINT('',#1517);
#1519=EDGE_CURVE('E178',#1518,#1518,#1516,.T.);
#1520=CARTESIAN_POINT('',(2.70000000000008,1.5,-4.44999999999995));
#1521=CARTESIAN_POINT('',(2.70000000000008,1.57291666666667,-4.44999999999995));
#1522=CARTESIAN_POINT('',(2.70000000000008,1.64583333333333,-4.44999999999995));
#1523=CARTESIAN_POINT('',(2.70000000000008,1.79166666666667,-4.44999999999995));
#1524=CARTESIAN_POINT('',(2.70000000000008,1.86458333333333,-4.44999999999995));
#1525=CARTESIAN_POINT('',(2.70000000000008,2.01041666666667,-4.44999999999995));
#1526=CARTESIAN_POINT('',(2.70000000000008,2.08333333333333,-4.44999999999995));
#1527=CARTESIAN_POINT('',(2.70000000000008,2.22916666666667,-4.44999999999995));
#1528=CARTESIAN_POINT('',(2.70000000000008,2.30208333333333,-4.44999999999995));
#1529=CARTESIAN_POINT('',(2.70000000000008,2.44791666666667,-4.44999999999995));
#1530=CARTESIAN_POINT('',(2.70000000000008,2.52083333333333,-4.44999999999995));
#1531=CARTESIAN_POINT('',(2.70000000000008,2.66666666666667,-4.44999999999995));
#1532=CARTESIAN_POINT('',(2.70000000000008,2.73958333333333,-4.44999999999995));
#1533=CARTESIAN_POINT('',(2.70000000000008,2.88541666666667,-4.44999999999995));
#1534=CARTESIAN_POINT('',(2.70000000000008,2.95833333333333,-4.44999999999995));
#1535=CARTESIAN_POINT('',(2.70000000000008,3.10416666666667,-4.44999999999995));
#1536=CARTESIAN_POINT('',(2.70000000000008,3.17708333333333,-4.44999999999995));
#1537=CARTESIAN_POINT('',(2.70000000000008,3.32291666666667,-4.44999999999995));
#1538=CARTESIAN_POINT('',(2.70000000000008,3.39583333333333,-4.44999999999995));
#1539=CARTESIAN_POINT('',(2.70000000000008,3.54166666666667,-4.44999999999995));
#1540=CARTESIAN_POINT('',(2.70000000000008,3.61458333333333,-4.44999999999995));
#1541=CARTESIAN_POINT('',(2.70000000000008,3.76041666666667,-4.44999999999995));
#1542=CARTESIAN_POINT('',(2.70000000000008,3.83333333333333,-4.44999999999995));
#1543=CARTESIAN_POINT('',(2.70000000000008,3.97916666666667,-4.44999999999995));
#1544=CARTESIAN_POINT('',(2.70000000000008,4.05208333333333,-4.44999999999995));
#1545=CARTESIAN_POINT('',(2.70000000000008,4.19791666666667,-4.44999999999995));
#1546=CARTESIAN_POINT('',(2.70000000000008,4.27083333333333,-4.44999999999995));
#1547=CARTESIAN_POINT('',(2.70000000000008,4.41666666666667,-4.44999999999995));
#1548=CARTESIAN_POINT('',(2.70000000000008,4.48958333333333,-4.44999999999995));
#1549=CARTESIAN_POINT('',(2.70000000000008,4.63541666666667,-4.44999999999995));
#1550=CARTESIAN_POINT('',(2.70000000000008,4.70833333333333,-4.44999999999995));
#1551=CARTESIAN_POINT('',(2.70000000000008,4.85416666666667,-4.44999999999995));
#1552=CARTESIAN_POINT('',(2.70000000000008,4.92708333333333,-4.44999999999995));
#1553=CARTESIAN_POINT('',(2.70000000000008,5.07291666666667,-4.44999999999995));
#1554=CARTESIAN_POINT('',(2.70000000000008,5.14583333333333,-4.44999999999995));
#1555=CARTESIAN_POINT('',(2.70000000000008,5.29166666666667,-4.44999999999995));
#1556=CARTESIAN_POINT('',(2.70000000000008,5.36458333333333,-4.44999999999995));
#1557=CARTESIAN_POINT('',(2.70000000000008,5.51041666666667,-4.44999999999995));
#1558=CARTESIAN_POINT('',(2.70000000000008,5.58333333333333,-4.44999999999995));
#1559=CARTESIAN_POINT('',(2.70000000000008,5.72916666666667,-4.44999999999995));
#1560=CARTESIAN_POINT('',(2.70000000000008,5.80208333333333,-4.44999999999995));
#1561=CARTESIAN_POINT('',(2.70000000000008,5.94791666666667,-4.44999999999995));
#1562=CARTESIAN_POINT('',(2.70000000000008,6.02083333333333,-4.44999999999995));
#1563=CARTESIAN_POINT('',(2.70000000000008,6.16666666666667,-4.44999999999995));
#1564=CARTESIAN_POINT('',(2.70000000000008,6.23958333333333,-4.44999999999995));
#1565=CARTESIAN_POINT('',(2.70000000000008,6.38541666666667,-4.44999999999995));
#1566=CARTESIAN_POINT('',(2.70000000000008,6.45833333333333,-4.44999999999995));
#1567=CARTESIAN_POINT('',(2.70000000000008,6.60416666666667,-4.44999999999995));
#1568=CARTESIAN_POINT('',(2.70000000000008,6.67708333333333,-4.44999999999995));
#1569=CARTESIAN_POINT('',(2.70000000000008,6.82291666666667,-4.44999999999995));
#1570=CARTESIAN_POINT('',(2.70000000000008,6.89583333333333,-4.44999999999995));
#1571=CARTESIAN_POINT('',(2.70000000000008,7.04166666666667,-4.44999999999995));
#1572=CARTESIAN_POINT('',(2.70000000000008,7.11458333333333,-4.44999999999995));
#1573=CARTESIAN_POINT('',(2.70000000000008,7.26041666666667,-4.44999999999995));
#1574=CARTESIAN_POINT('',(2.70000000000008,7.33333333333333,-4.44999999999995));
#1575=CARTESIAN_POINT('',(2.70000000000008,7.47916666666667,-4.44999999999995));
#1576=CARTESIAN_POINT('',(2.70000000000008,7.55208333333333,-4.44999999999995));
#1577=CARTESIAN_POINT('',(2.70000000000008,7.69791666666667,-4.44999999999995));
#1578=CARTESIAN_POINT('',(2.70000000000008,7.77083333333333,-4.44999999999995));
#1579=CARTESIAN_POINT('',(2.70000000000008,7.91666666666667,-4.44999999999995));
#1580=CARTESIAN_POINT('',(2.70000000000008,7.98958333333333,-4.44999999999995));
#1581=CARTESIAN_POINT('',(2.70000000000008,8.13541666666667,-4.44999999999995));
#1582=CARTESIAN_POINT('',(2.70000000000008,8.20833333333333,-4.44999999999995));
#1583=CARTESIAN_POINT('',(2.70000000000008,8.35416666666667,-4.44999999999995));
#1584=CARTESIAN_POINT('',(2.70000000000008,8.42708333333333,-4.44999999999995));
#1585=CARTESIAN_POINT('',(2.70000000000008,8.5,-4.44999999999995));
#1586=B_SPLINE_CURVE_WITH_KNOTS('',3,(#1520,#1521,#1522,#1523,#1524,#1525,#1526,#1527,#1528,
#1529,#1530,#1531,#1532,#1533,#1534,#1535,#1536,#1537,#1538,#1539,#1540,#1541,#1542,#1543,#1544,
#1545,#1546,#1547,#1548,#1549,#1550,#1551,#1552,#1553,#1554,#1555,#1556,#1557,#1558,#1559,#1560,
#1561,#1562,#1563,#1564,#1565,#1566,#1567,#1568,#1569,#1570,#1571,#1572,#1573,#1574,#1575,#1576,
#1577,#1578,#1579,#1580,#1581,#1582,#1583,#1584,#1585),.UNSPECIFIED.,.F.,.F.,(4,2,2,2,2,2,2,2,2,
2,2,2,2,2,2,2,2,2,2,2,2,2,2,2,2,2,2,2,2,2,2,2,4),(0.,0.21875,0.4375,0.65625,0.875,1.09375,
1.3125,1.53125,1.75,1.96875,2.1875,2.40625,2.625,2.84375,3.0625,3.28125,3.5,3.71875,3.9375,
4.15625,4.375,4.59375,4.8125,5.03125,5.25,5.46875,5.6875,5.90625,6.125,6.34375,6.5625,6.78125,
7.),.UNSPECIFIED.);
#1587=EDGE_CURVE('BSEAM493',#1518,#187,#1586,.T.);
#1588=ORIENTED_EDGE('',*,*,#1519,.F.);
#1589=ORIENTED_EDGE('',*,*,#188,.T.);
#1590=ORIENTED_EDGE('',*,*,#1587,.T.);
#1591=ORIENTED_EDGE('',*,*,#1587,.F.);
#1592=EDGE_LOOP('',(#1588,#1590,#1589,#1591));
#1593=FACE_BOUND('',#1592,.T.);
#1594=ADVANCED_FACE('F493',(#1593),#1511,.F.);
#1595=CARTESIAN_POINT('',(2.70000000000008,1.5,-5.19999999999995));
#1596=DIRECTION('',(0.,1.,0.));
#1597=DIRECTION('',(0.,0.,1.));
#1598=AXIS2_PLACEMENT_3D('',#1595,#1596,#1597);
#1599=PLANE('',#1598);
#1600=ORIENTED_EDGE('',*,*,#1519,.T.);
#1601=EDGE_LOOP('',(#1600));
#1602=FACE_BOUND('',#1601,.T.);
#1603=ADVANCED_FACE('F502',(#1602),#1599,.T.);
#1604=CARTESIAN_POINT('',(10.2,1.5,-10.2));
#1605=DIRECTION('',(0.,1.,0.));
#1606=DIRECTION('',(0.,0.,1.));
#1607=AXIS2_PLACEMENT_3D('',#1604,#1605,#1606);
#1608=CYLINDRICAL_SURFACE('',#1607,0.75);
#1609=CARTESIAN_POINT('',(10.2,1.5,-10.2));
#1610=DIRECTION('',(0.,1.,0.));
#1611=DIRECTION('',(0.,0.,1.));
#1612=AXIS2_PLACEMENT_3D('',#1609,#1610,#1611);
#1613=CIRCLE('',#1612,0.75);
#1614=CARTESIAN_POINT('',(10.2,1.5,-9.45));
#1615=VERTEX_POINT('',#1614);
#1616=EDGE_CURVE('E184',#1615,#1615,#1613,.T.);
#1617=CARTESIAN_POINT('',(10.2,1.5,-9.45));
#1618=CARTESIAN_POINT('',(10.2,1.57291666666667,-9.45));
#1619=CARTESIAN_POINT('',(10.2,1.64583333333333,-9.45));
#1620=CARTESIAN_POINT('',(10.2,1.79166666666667,-9.45));
#1621=CARTESIAN_POINT('',(10.2,1.86458333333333,-9.45));
#1622=CARTESIAN_POINT('',(10.2,2.01041666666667,-9.45));
#1623=CARTESIAN_POINT('',(10.2,2.08333333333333,-9.45));
#1624=CARTESIAN_POINT('',(10.2,2.22916666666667,-9.45));
#1625=CARTESIAN_POINT('',(10.2,2.30208333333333,-9.45));
#1626=CARTESIAN_POINT('',(10.2,2.44791666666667,-9.45));
#1627=CARTESIAN_POINT('',(10.2,2.52083333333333,-9.45));
#1628=CARTESIAN_POINT('',(10.2,2.66666666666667,-9.45));
#1629=CARTESIAN_POINT('',(10.2,2.73958333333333,-9.45));
#1630=CARTESIAN_POINT('',(10.2,2.88541666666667,-9.45));
#1631=CARTESIAN_POINT('',(10.2,2.95833333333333,-9.45));
#1632=CARTESIAN_POINT('',(10.2,3.10416666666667,-9.45));
#1633=CARTESIAN_POINT('',(10.2,3.17708333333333,-9.45));
#1634=CARTESIAN_POINT('',(10.2,3.32291666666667,-9.45));
#1635=CARTESIAN_POINT('',(10.2,3.39583333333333,-9.45));
#1636=CARTESIAN_POINT('',(10.2,3.54166666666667,-9.45));
#1637=CARTESIAN_POINT('',(10.2,3.61458333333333,-9.45));
#1638=CARTESIAN_POINT('',(10.2,3.76041666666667,-9.45));
#1639=CARTESIAN_POINT('',(10.2,3.83333333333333,-9.45));
#1640=CARTESIAN_POINT('',(10.2,3.97916666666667,-9.45));
#1641=CARTESIAN_POINT('',(10.2,4.05208333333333,-9.45));
#1642=CARTESIAN_POINT('',(10.2,4.19791666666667,-9.45));
#1643=CARTESIAN_POINT('',(10.2,4.27083333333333,-9.45));
#1644=CARTESIAN_POINT('',(10.2,4.41666666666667,-9.45));
#1645=CARTESIAN_POINT('',(10.2,4.48958333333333,-9.45));
#1646=CARTESIAN_POINT('',(10.2,4.63541666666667,-9.45));
#1647=CARTESIAN_POINT('',(10.2,4.70833333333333,-9.45));
#1648=CARTESIAN_POINT('',(10.2,4.85416666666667,-9.45));
#1649=CARTESIAN_POINT('',(10.2,4.92708333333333,-9.45));
#1650=CARTESIAN_POINT('',(10.2,5.07291666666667,-9.45));
#1651=CARTESIAN_POINT('',(10.2,5.14583333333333,-9.45));
#1652=CARTESIAN_POINT('',(10.2,5.29166666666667,-9.45));
#1653=CARTESIAN_POINT('',(10.2,5.36458333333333,-9.45));
#1654=CARTESIAN_POINT('',(10.2,5.51041666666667,-9.45));
#1655=CARTESIAN_POINT('',(10.2,5.58333333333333,-9.45));
#1656=CARTESIAN_POINT('',(10.2,5.72916666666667,-9.45));
#1657=CARTESIAN_POINT('',(10.2,5.80208333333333,-9.45));
#1658=CARTESIAN_POINT('',(10.2,5.94791666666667,-9.45));
#1659=CARTESIAN_POINT('',(10.2,6.02083333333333,-9.45));
#1660=CARTESIAN_POINT('',(10.2,6.16666666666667,-9.45));
#1661=CARTESIAN_POINT('',(10.2,6.23958333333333,-9.45));
#1662=CARTESIAN_POINT('',(10.2,6.38541666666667,-9.45));
#1663=CARTESIAN_POINT('',(10.2,6.45833333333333,-9.45));
#1664=CARTESIAN_POINT('',(10.2,6.60416666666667,-9.45));
#1665=CARTESIAN_POINT('',(10.2,6.67708333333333,-9.45));
#1666=CARTESIAN_POINT('',(10.2,6.82291666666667,-9.45));
#1667=CARTESIAN_POINT('',(10.2,6.89583333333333,-9.45));
#1668=CARTESIAN_POINT('',(10.2,7.04166666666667,-9.45));
#1669=CARTESIAN_POINT('',(10.2,7.11458333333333,-9.45));
#1670=CARTESIAN_POINT('',(10.2,7.26041666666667,-9.45));
#1671=CARTESIAN_POINT('',(10.2,7.33333333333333,-9.45));
#1672=CARTESIAN_POINT('',(10.2,7.47916666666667,-9.45));
#1673=CARTESIAN_POINT('',(10.2,7.55208333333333,-9.45));
#1674=CARTESIAN_POINT('',(10.2,7.69791666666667,-9.45));
#1675=CARTESIAN_POINT('',(10.2,7.77083333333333,-9.45));
#1676=CARTESIAN_POINT('',(10.2,7.91666666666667,-9.45));
#1677=CARTESIAN_POINT('',(10.2,7.98958333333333,-9.45));
#1678=CARTESIAN_POINT('',(10.2,8.13541666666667,-9.45));
#1679=CARTESIAN_POINT('',(10.2,8.20833333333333,-9.45));
#1680=CARTESIAN_POINT('',(10.2,8.35416666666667,-9.45));
#1681=CARTESIAN_POINT('',(10.2,8.42708333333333,-9.45));
#1682=CARTESIAN_POINT('',(10.2,8.5,-9.45));
#1683=B_SPLINE_CURVE_WITH_KNOTS('',3,(#1617,#1618,#1619,#1620,#1621,#1622,#1623,#1624,#1625,
#1626,#1627,#1628,#1629,#1630,#1631,#1632,#1633,#1634,#1635,#1636,#1637,#1638,#1639,#1640,#1641,
#1642,#1643,#1644,#1645,#1646,#1647,#1648,#1649,#1650,#1651,#1652,#1653,#1654,#1655,#1656,#1657,
#1658,#1659,#1660,#1661,#1662,#1663,#1664,#1665,#1666,#1667,#1668,#1669,#1670,#1671,#1672,#1673,
#1674,#1675,#1676,#1677,#1678,#1679,#1680,#1681,#1682),.UNSPECIFIED.,.F.,.F.,(4,2,2,2,2,2,2,2,2,
2,2,2,2,2,2,2,2,2,2,2,2,2,2,2,2,2,2,2,2,2,2,2,4),(0.,0.21875,0.4375,0.65625,0.875,1.09375,
1.3125,1.53125,1.75,1.96875,2.1875,2.40625,2.625,2.84375,3.0625,3.28125,3.5,3.71875,3.9375,
4.15625,4.375,4.59375,4.8125,5.03125,5.25,5.46875,5.6875,5.90625,6.125,6.34375,6.5625,6.78125,
7.),.UNSPECIFIED.);
#1684=EDGE_CURVE('BSEAM511',#1615,#176,#1683,.T.);
#1685=ORIENTED_EDGE('',*,*,#1616,.F.);
#1686=ORIENTED_EDGE('',*,*,#177,.T.);
#1687=ORIENTED_EDGE('',*,*,#1684,.T.);
#1688=ORIENTED_EDGE('',*,*,#1684,.F.);
#1689=EDGE_LOOP('',(#1685,#1687,#1686,#1688));
#1690=FACE_BOUND('',#1689,.T.);
#1691=ADVANCED_FACE('F511',(#1690),#1608,.F.);
#1692=CARTESIAN_POINT('',(10.2,1.5,-10.2));
#1693=DIRECTION('',(0.,1.,0.));
#1694=DIRECTION('',(0.,0.,1.));
#1695=AXIS2_PLACEMENT_3D('',#1692,#1693,#1694);
#1696=PLANE('',#1695);
#1697=ORIENTED_EDGE('',*,*,#1616,.T.);
#1698=EDGE_LOOP('',(#1697));
#1699=FACE_BOUND('',#1698,.T.);
#1700=ADVANCED_FACE('F520',(#1699),#1696,.T.);
#1701=CARTESIAN_POINT('',(10.2000000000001,1.5,-7.7));
#1702=DIRECTION('',(0.,1.,0.));
#1703=DIRECTION('',(0.,0.,1.));
#1704=AXIS2_PLACEMENT_3D('',#1701,#1702,#1703);
#1705=CYLINDRICAL_SURFACE('',#1704,0.75);
#1706=CARTESIAN_POINT('',(10.2000000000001,1.5,-7.7));
#1707=DIRECTION('',(0.,1.,0.));
#1708=DIRECTION('',(0.,0.,1.));
#1709=AXIS2_PLACEMENT_3D('',#1706,#1707,#1708);
#1710=CIRCLE('',#1709,0.75);
#1711=CARTESIAN_POINT('',(10.2000000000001,1.5,-6.95));
#1712=VERTEX_POINT('',#1711);
#1713=EDGE_CURVE('E190',#1712,#1712,#1710,.T.);
#1714=CARTESIAN_POINT('',(10.2000000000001,1.5,-6.95));
#1715=CARTESIAN_POINT('',(10.2000000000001,1.57291666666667,-6.95));
#1716=CARTESIAN_POINT('',(10.2000000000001,1.64583333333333,-6.95));
#1717=CARTESIAN_POINT('',(10.2000000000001,1.79166666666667,-6.95));
#1718=CARTESIAN_POINT('',(10.2000000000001,1.86458333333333,-6.95));
#1719=CARTESIAN_POINT('',(10.2000000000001,2.01041666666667,-6.95));
#1720=CARTESIAN_POINT('',(10.2000000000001,2.08333333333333,-6.95));
#1721=CARTESIAN_POINT('',(10.2000000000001,2.22916666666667,-6.95));
#1722=CARTESIAN_POINT('',(10.2000000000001,2.30208333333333,-6.95));
#1723=CARTESIAN_POINT('',(10.2000000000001,2.44791666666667,-6.95));
#1724=CARTESIAN_POINT('',(10.2000000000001,2.52083333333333,-6.95));
#1725=CARTESIAN_POINT('',(10.2000000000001,2.66666666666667,-6.95));
#1726=CARTESIAN_POINT('',(10.2000000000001,2.73958333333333,-6.95));
#1727=CARTESIAN_POINT('',(10.2000000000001,2.88541666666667,-6.95));
#1728=CARTESIAN_POINT('',(10.2000000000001,2.95833333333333,-6.95));
#1729=CARTESIAN_POINT('',(10.2000000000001,3.10416666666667,-6.95));
#1730=CARTESIAN_POINT('',(10.2000000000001,3.17708333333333,-6.95));
#1731=CARTESIAN_POINT('',(10.2000000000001,3.32291666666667,-6.95));
#1732=CARTESIAN_POINT('',(10.2000000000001,3.39583333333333,-6.95));
#1733=CARTESIAN_POINT('',(10.2000000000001,3.54166666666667,-6.95));
#1734=CARTESIAN_POINT('',(10.2000000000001,3.61458333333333,-6.95));
#1735=CARTESIAN_POINT('',(10.2000000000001,3.76041666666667,-6.95));
#1736=CARTESIAN_POINT('',(10.2000000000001,3.83333333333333,-6.95));
#1737=CARTESIAN_POINT('',(10.2000000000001,3.97916666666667,-6.95));
#1738=CARTESIAN_POINT('',(10.2000000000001,4.05208333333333,-6.95));
#1739=CARTESIAN_POINT('',(10.2000000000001,4.19791666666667,-6.95));
#1740=CARTESIAN_POINT('',(10.2000000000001,4.27083333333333,-6.95));
#1741=CARTESIAN_POINT('',(10.2000000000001,4.41666666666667,-6.95));
#1742=CARTESIAN_POINT('',(10.2000000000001,4.48958333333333,-6.95));
#1743=CARTESIAN_POINT('',(10.2000000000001,4.63541666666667,-6.95));
#1744=CARTESIAN_POINT('',(10.2000000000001,4.70833333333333,-6.95));
#1745=CARTESIAN_POINT('',(10.2000000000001,4.85416666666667,-6.95));
#1746=CARTESIAN_POINT('',(10.2000000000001,4.92708333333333,-6.95));
#1747=CARTESIAN_POINT('',(10.2000000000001,5.07291666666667,-6.95));
#1748=CARTESIAN_POINT('',(10.2000000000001,5.14583333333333,-6.95));
#1749=CARTESIAN_POINT('',(10.2000000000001,5.29166666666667,-6.95));
#1750=CARTESIAN_POINT('',(10.2000000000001,5.36458333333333,-6.95));
#1751=CARTESIAN_POINT('',(10.2000000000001,5.51041666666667,-6.95));
#1752=CARTESIAN_POINT('',(10.2000000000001,5.58333333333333,-6.95));
#1753=CARTESIAN_POINT('',(10.2000000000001,5.72916666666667,-6.95));
#1754=CARTESIAN_POINT('',(10.2000000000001,5.80208333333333,-6.95));
#1755=CARTESIAN_POINT('',(10.2000000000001,5.94791666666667,-6.95));
#1756=CARTESIAN_POINT('',(10.2000000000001,6.02083333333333,-6.95));
#1757=CARTESIAN_POINT('',(10.2000000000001,6.16666666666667,-6.95));
#1758=CARTESIAN_POINT('',(10.2000000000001,6.23958333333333,-6.95));
#1759=CARTESIAN_POINT('',(10.2000000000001,6.38541666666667,-6.95));
#1760=CARTESIAN_POINT('',(10.2000000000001,6.45833333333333,-6.95));
#1761=CARTESIAN_POINT('',(10.2000000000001,6.60416666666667,-6.95));
#1762=CARTESIAN_POINT('',(10.2000000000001,6.67708333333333,-6.95));
#1763=CARTESIAN_POINT('',(10.2000000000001,6.82291666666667,-6.95));
#1764=CARTESIAN_POINT('',(10.2000000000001,6.89583333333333,-6.95));
#1765=CARTESIAN_POINT('',(10.2000000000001,7.04166666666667,-6.95));
#1766=CARTESIAN_POINT('',(10.2000000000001,7.11458333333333,-6.95));
#1767=CARTESIAN_POINT('',(10.2000000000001,7.26041666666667,-6.95));
#1768=CARTESIAN_POINT('',(10.2000000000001,7.33333333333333,-6.95));
#1769=CARTESIAN_POINT('',(10.2000000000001,7.47916666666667,-6.95));
#1770=CARTESIAN_POINT('',(10.2000000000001,7.55208333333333,-6.95));
#1771=CARTESIAN_POINT('',(10.2000000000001,7.69791666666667,-6.95));
#1772=CARTESIAN_POINT('',(10.2000000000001,7.77083333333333,-6.95));
#1773=CARTESIAN_POINT('',(10.2000000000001,7.91666666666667,-6.95));
#1774=CARTESIAN_POINT('',(10.2000000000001,7.98958333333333,-6.95));
#1775=CARTESIAN_POINT('',(10.2000000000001,8.13541666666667,-6.95));
#1776=CARTESIAN_POINT('',(10.2000000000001,8.20833333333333,-6.95));
#1777=CARTESIAN_POINT('',(10.2000000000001,8.35416666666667,-6.95));
#1778=CARTESIAN_POINT('',(10.2000000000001,8.42708333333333,-6.95));
#1779=CARTESIAN_POINT('',(10.2000000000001,8.5,-6.95));
#1780=B_SPLINE_CURVE_WITH_KNOTS('',3,(#1714,#1715,#1716,#1717,#1718,#1719,#1720,#1721,#1722,
#1723,#1724,#1725,#1726,#1727,#1728,#1729,#1730,#1731,#1732,#1733,#1734,#1735,#1736,#1737,#1738,
#1739,#1740,#1741,#1742,#1743,#1744,#1745,#1746,#1747,#1748,#1749,#1750,#1751,#1752,#1753,#1754,
#1755,#1756,#1757,#1758,#1759,#1760,#1761,#1762,#1763,#1764,#1765,#1766,#1767,#1768,#1769,#1770,
#1771,#1772,#1773,#1774,#1775,#1776,#1777,#1778,#1779),.UNSPECIFIED.,.F.,.F.,(4,2,2,2,2,2,2,2,2,
2,2,2,2,2,2,2,2,2,2,2,2,2,2,2,2,2,2,2,2,2,2,2,4),(0.,0.21875,0.4375,0.65625,0.875,1.09375,
1.3125,1.53125,1.75,1.96875,2.1875,2.40625,2.625,2.84375,3.0625,3.28125,3.5,3.71875,3.9375,
4.15625,4.375,4.59375,4.8125,5.03125,5.25,5.46875,5.6875,5.90625,6.125,6.34375,6.5625,6.78125,
7.),.UNSPECIFIED.);
#1781=EDGE_CURVE('BSEAM529',#1712,#165,#1780,.T.);
#1782=ORIENTED_EDGE('',*,*,#1713,.F.);
#1783=ORIENTED_EDGE('',*,*,#166,.T.);
#1784=ORIENTED_EDGE('',*,*,#1781,.T.);
#1785=ORIENTED_EDGE('',*,*,#1781,.F.);
#1786=EDGE_LOOP('',(#1782,#1784,#1783,#1785));
#1787=FACE_BOUND('',#1786,.T.);
#1788=ADVANCED_FACE('F529',(#1787),#1705,.F.);
#1789=CARTESIAN_POINT('',(10.2000000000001,1.5,-7.7));
#1790=DIRECTION('',(0.,1.,0.));
#1791=DIRECTION('',(0.,0.,1.));
#1792=AXIS2_PLACEMENT_3D('',#1789,#1790,#1791);
#1793=PLANE('',#1792);
#1794=ORIENTED_EDGE('',*,*,#1713,.T.);
#1795=EDGE_LOOP('',(#1794));
#1796=FACE_BOUND('',#1795,.T.);
#1797=ADVANCED_FACE('F210',(#1796),#1793,.T.);
#1798=CARTESIAN_POINT('',(10.2000000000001,1.5,-5.2));
#1799=DIRECTION('',(0.,1.,0.));
#1800=DIRECTION('',(0.,0.,1.));
#1801=AXIS2_PLACEMENT_3D('',#1798,#1799,#1800);
#1802=CYLINDRICAL_SURFACE('',#1801,0.75);
#1803=CARTESIAN_POINT('',(10.2000000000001,1.5,-5.2));
#1804=DIRECTION('',(0.,1.,0.));
#1805=DIRECTION('',(0.,0.,1.));
#1806=AXIS2_PLACEMENT_3D('',#1803,#1804,#1805);
#1807=CIRCLE('',#1806,0.75);
#1808=CARTESIAN_POINT('',(10.2000000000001,1.5,-4.45));
#1809=VERTEX_POINT('',#1808);
#1810=EDGE_CURVE('E196',#1809,#1809,#1807,.T.);
#1811=CARTESIAN_POINT('',(10.2000000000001,1.5,-4.45));
#1812=CARTESIAN_POINT('',(10.2000000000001,1.57291666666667,-4.45));
#1813=CARTESIAN_POINT('',(10.2000000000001,1.64583333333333,-4.45));
#1814=CARTESIAN_POINT('',(10.2000000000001,1.79166666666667,-4.45));
#1815=CARTESIAN_POINT('',(10.2000000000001,1.86458333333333,-4.45));
#1816=CARTESIAN_POINT('',(10.2000000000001,2.01041666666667,-4.45));
#1817=CARTESIAN_POINT('',(10.2000000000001,2.08333333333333,-4.45));
#1818=CARTESIAN_POINT('',(10.2000000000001,2.22916666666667,-4.45));
#1819=CARTESIAN_POINT('',(10.2000000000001,2.30208333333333,-4.45));
#1820=CARTESIAN_POINT('',(10.2000000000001,2.44791666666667,-4.45));
#1821=CARTESIAN_POINT('',(10.2000000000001,2.52083333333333,-4.45));
#1822=CARTESIAN_POINT('',(10.2000000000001,2.66666666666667,-4.45));
#1823=CARTESIAN_POINT('',(10.2000000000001,2.73958333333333,-4.45));
#1824=CARTESIAN_POINT('',(10.2000000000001,2.88541666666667,-4.45));
#1825=CARTESIAN_POINT('',(10.2000000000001,2.95833333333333,-4.45));
#1826=CARTESIAN_POINT('',(10.2000000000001,3.10416666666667,-4.45));
#1827=CARTESIAN_POINT('',(10.2000000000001,3.17708333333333,-4.45));
#1828=CARTESIAN_POINT('',(10.2000000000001,3.32291666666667,-4.45));
#1829=CARTESIAN_POINT('',(10.2000000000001,3.39583333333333,-4.45));
#1830=CARTESIAN_POINT('',(10.2000000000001,3.54166666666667,-4.45));
#1831=CARTESIAN_POINT('',(10.2000000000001,3.61458333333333,-4.45));
#1832=CARTESIAN_POINT('',(10.2000000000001,3.76041666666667,-4.45));
#1833=CARTESIAN_POINT('',(10.2000000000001,3.83333333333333,-4.45));
#1834=CARTESIAN_POINT('',(10.2000000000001,3.97916666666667,-4.45));
#1835=CARTESIAN_POINT('',(10.2000000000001,4.05208333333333,-4.45));
#1836=CARTESIAN_POINT('',(10.2000000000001,4.19791666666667,-4.45));
#1837=CARTESIAN_POINT('',(10.2000000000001,4.27083333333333,-4.45));
#1838=CARTESIAN_POINT('',(10.2000000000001,4.41666666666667,-4.45));
#1839=CARTESIAN_POINT('',(10.2000000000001,4.48958333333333,-4.45));
#1840=CARTESIAN_POINT('',(10.2000000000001,4.63541666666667,-4.45));
#1841=CARTESIAN_POINT('',(10.2000000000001,4.70833333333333,-4.45));
#1842=CARTESIAN_POINT('',(10.2000000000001,4.85416666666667,-4.45));
#1843=CARTESIAN_POINT('',(10.2000000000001,4.92708333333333,-4.45));
#1844=CARTESIAN_POINT('',(10.2000000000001,5.07291666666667,-4.45));
#1845=CARTESIAN_POINT('',(10.2000000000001,5.14583333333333,-4.45));
#1846=CARTESIAN_POINT('',(10.2000000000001,5.29166666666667,-4.45));
#1847=CARTESIAN_POINT('',(10.2000000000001,5.36458333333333,-4.45));
#1848=CARTESIAN_POINT('',(10.2000000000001,5.51041666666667,-4.45));
#1849=CARTESIAN_POINT('',(10.2000000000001,5.58333333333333,-4.45));
#1850=CARTESIAN_POINT('',(10.2000000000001,5.72916666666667,-4.45));
#1851=CARTESIAN_POINT('',(10.2000000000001,5.80208333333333,-4.45));
#1852=CARTESIAN_POINT('',(10.2000000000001,5.94791666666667,-4.45));
#1853=CARTESIAN_POINT('',(10.2000000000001,6.02083333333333,-4.45));
#1854=CARTESIAN_POINT('',(10.2000000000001,6.16666666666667,-4.45));
#1855=CARTESIAN_POINT('',(10.2000000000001,6.23958333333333,-4.45));
#1856=CARTESIAN_POINT('',(10.2000000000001,6.38541666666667,-4.45));
#1857=CARTESIAN_POINT('',(10.2000000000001,6.45833333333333,-4.45));
#1858=CARTESIAN_POINT('',(10.2000000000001,6.60416666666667,-4.45));
#1859=CARTESIAN_POINT('',(10.2000000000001,6.67708333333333,-4.45));
#1860=CARTESIAN_POINT('',(10.2000000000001,6.82291666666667,-4.45));
#1861=CARTESIAN_POINT('',(10.2000000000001,6.89583333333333,-4.45));
#1862=CARTESIAN_POINT('',(10.2000000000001,7.04166666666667,-4.45));
#1863=CARTESIAN_POINT('',(10.2000000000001,7.11458333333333,-4.45));
#1864=CARTESIAN_POINT('',(10.2000000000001,7.26041666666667,-4.45));
#1865=CARTESIAN_POINT('',(10.2000000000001,7.33333333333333,-4.45));
#1866=CARTESIAN_POINT('',(10.2000000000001,7.47916666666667,-4.45));
#1867=CARTESIAN_POINT('',(10.2000000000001,7.55208333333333,-4.45));
#1868=CARTESIAN_POINT('',(10.2000000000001,7.69791666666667,-4.45));
#1869=CARTESIAN_POINT('',(10.2000000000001,7.77083333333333,-4.45));
#1870=CARTESIAN_POINT('',(10.2000000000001,7.91666666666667,-4.45));
#1871=CARTESIAN_POINT('',(10.2000000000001,7.98958333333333,-4.45));
#1872=CARTESIAN_POINT('',(10.2000000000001,8.13541666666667,-4.45));
#1873=CARTESIAN_POINT('',(10.2000000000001,8.20833333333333,-4.45));
#1874=CARTESIAN_POINT('',(10.2000000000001,8.35416666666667,-4.45));
#1875=CARTESIAN_POINT('',(10.2000000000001,8.42708333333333,-4.45));
#1876=CARTESIAN_POINT('',(10.2000000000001,8.5,-4.45));
#1877=B_SPLINE_CURVE_WITH_KNOTS('',3,(#1811,#1812,#1813,#1814,#1815,#1816,#1817,#1818,#1819,
#1820,#1821,#1822,#1823,#1824,#1825,#1826,#1827,#1828,#1829,#1830,#1831,#1832,#1833,#1834,#1835,
#1836,#1837,#1838,#1839,#1840,#1841,#1842,#1843,#1844,#1845,#1846,#1847,#1848,#1849,#1850,#1851,
#1852,#1853,#1854,#1855,#1856,#1857,#1858,#1859,#1860,#1861,#1862,#1863,#1864,#1865,#1866,#1867,
#1868,#1869,#1870,#1871,#1872,#1873,#1874,#1875,#1876),.UNSPECIFIED.,.F.,.F.,(4,2,2,2,2,2,2,2,2,
2,2,2,2,2,2,2,2,2,2,2,2,2,2,2,2,2,2,2,2,2,2,2,4),(0.,0.21875,0.4375,0.65625,0.875,1.09375,
1.3125,1.53125,1.75,1.96875,2.1875,2.40625,2.625,2.84375,3.0625,3.28125,3.5,3.71875,3.9375,
4.15625,4.375,4.59375,4.8125,5.03125,5.25,5.46875,5.6875,5.90625,6.125,6.34375,6.5625,6.78125,
7.),.UNSPECIFIED.);
#1878=EDGE_CURVE('BSEAM207',#1809,#154,#1877,.T.);
#1879=ORIENTED_EDGE('',*,*,#1810,.F.);
#1880=ORIENTED_EDGE('',*,*,#155,.T.);
#1881=ORIENTED_EDGE('',*,*,#1878,.T.);
#1882=ORIENTED_EDGE('',*,*,#1878,.F.);
#1883=EDGE_LOOP('',(#1879,#1881,#1880,#1882));
#1884=FACE_BOUND('',#1883,.T.);
#1885=ADVANCED_FACE('F207',(#1884),#1802,.F.);
#1886=CARTESIAN_POINT('',(10.2000000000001,1.5,-5.2));
#1887=DIRECTION('',(0.,1.,0.));
#1888=DIRECTION('',(0.,0.,1.));
#1889=AXIS2_PLACEMENT_3D('',#1886,#1887,#1888);
#1890=PLANE('',#1889);
#1891=ORIENTED_EDGE('',*,*,#1810,.T.);
#1892=EDGE_LOOP('',(#1891));
#1893=FACE_BOUND('',#1892,.T.);
#1894=ADVANCED_FACE('F205',(#1893),#1890,.T.);
#1895=CLOSED_SHELL('',(#58,#89,#120,#142,#330,#342,#430,#439,#527,#536,#624,#633,#721,#730,#818,
#827,#915,#924,#1012,#1021,#1109,#1118,#1206,#1215,#1303,#1312,#1400,#1409,#1497,#1506,#1594,
#1603,#1691,#1700,#1788,#1797,#1885,#1894));
#1896=MANIFOLD_SOLID_BREP('B2',#1895);
#1897=ADVANCED_BREP_SHAPE_REPRESENTATION('',(#18,#1896),#14);
#1898=SHAPE_DEFINITION_REPRESENTATION(#9,#1897);
ENDSEC;
END-ISO-10303-21;
